VERSION 5.8 ;
BUSBITCHARS "[]" ;
DIVIDERCHAR "/" ;
UNITS
    DATABASE MICRONS 1000 ;
END UNITS

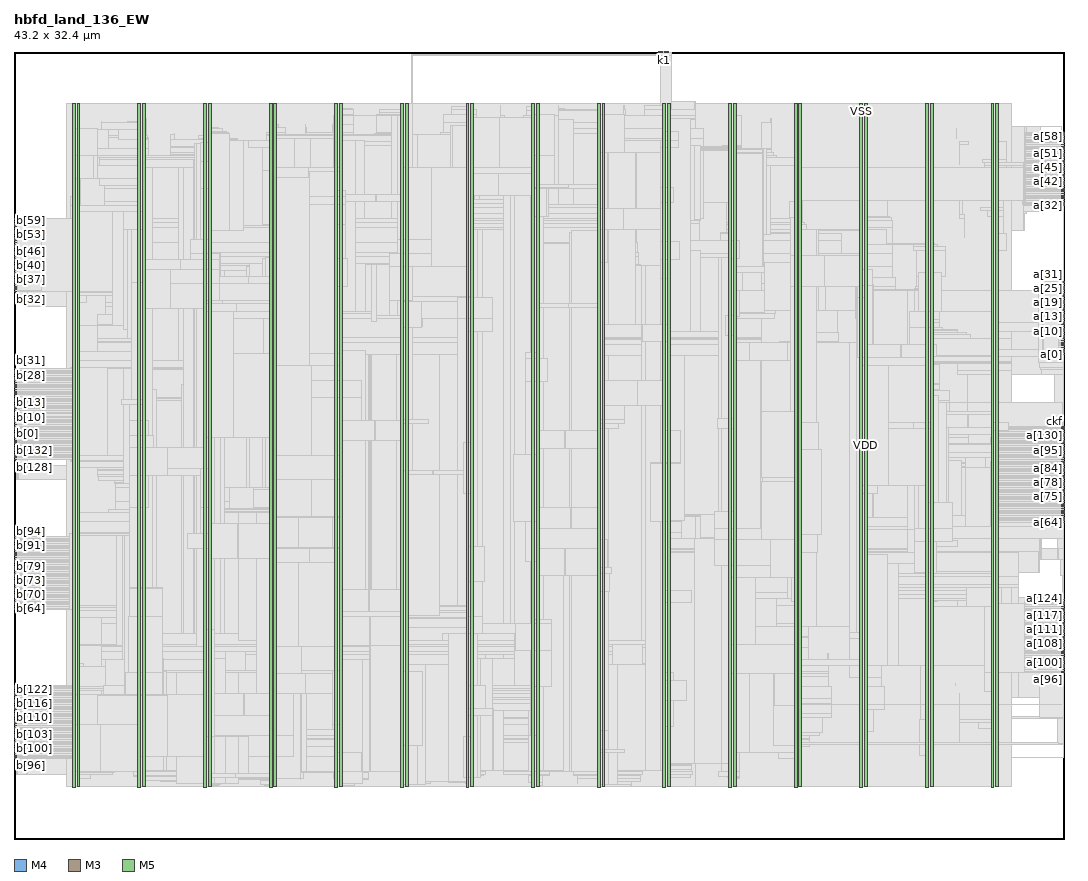
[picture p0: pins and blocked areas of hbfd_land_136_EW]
MACRO hbfd_land_136_EW
  FOREIGN hbfd_land_136_EW 0 0 ;
  CLASS BLOCK ;
  SIZE 43.2 BY 32.4 ;
  PIN a[0]
    DIRECTION INPUT ;
    USE SIGNAL ;
    PORT
      LAYER M4 ;
        RECT  43.116 19.92 43.2 19.944 ;
    END
  END a[0]
  PIN a[100]
    DIRECTION INPUT ;
    USE SIGNAL ;
    PORT
      LAYER M4 ;
        RECT  43.116 7.248 43.2 7.272 ;
    END
  END a[100]
  PIN a[101]
    DIRECTION INPUT ;
    USE SIGNAL ;
    PORT
      LAYER M4 ;
        RECT  43.116 7.344 43.2 7.368 ;
    END
  END a[101]
  PIN a[102]
    DIRECTION INPUT ;
    USE SIGNAL ;
    PORT
      LAYER M4 ;
        RECT  43.116 7.44 43.2 7.464 ;
    END
  END a[102]
  PIN a[103]
    DIRECTION INPUT ;
    USE SIGNAL ;
    PORT
      LAYER M4 ;
        RECT  43.116 7.536 43.2 7.56 ;
    END
  END a[103]
  PIN a[104]
    DIRECTION INPUT ;
    USE SIGNAL ;
    PORT
      LAYER M4 ;
        RECT  43.116 7.632 43.2 7.656 ;
    END
  END a[104]
  PIN a[105]
    DIRECTION INPUT ;
    USE SIGNAL ;
    PORT
      LAYER M4 ;
        RECT  43.116 7.728 43.2 7.752 ;
    END
  END a[105]
  PIN a[106]
    DIRECTION INPUT ;
    USE SIGNAL ;
    PORT
      LAYER M4 ;
        RECT  43.116 7.824 43.2 7.848 ;
    END
  END a[106]
  PIN a[107]
    DIRECTION INPUT ;
    USE SIGNAL ;
    PORT
      LAYER M4 ;
        RECT  43.116 7.92 43.2 7.944 ;
    END
  END a[107]
  PIN a[108]
    DIRECTION INPUT ;
    USE SIGNAL ;
    PORT
      LAYER M4 ;
        RECT  43.116 8.016 43.2 8.04 ;
    END
  END a[108]
  PIN a[109]
    DIRECTION INPUT ;
    USE SIGNAL ;
    PORT
      LAYER M4 ;
        RECT  43.116 8.112 43.2 8.136 ;
    END
  END a[109]
  PIN a[10]
    DIRECTION INPUT ;
    USE SIGNAL ;
    PORT
      LAYER M4 ;
        RECT  43.116 20.88 43.2 20.904 ;
    END
  END a[10]
  PIN a[110]
    DIRECTION INPUT ;
    USE SIGNAL ;
    PORT
      LAYER M4 ;
        RECT  43.116 8.208 43.2 8.232 ;
    END
  END a[110]
  PIN a[111]
    DIRECTION INPUT ;
    USE SIGNAL ;
    PORT
      LAYER M4 ;
        RECT  43.116 8.304 43.2 8.328 ;
    END
  END a[111]
  PIN a[112]
    DIRECTION INPUT ;
    USE SIGNAL ;
    PORT
      LAYER M4 ;
        RECT  43.116 8.4 43.2 8.424 ;
    END
  END a[112]
  PIN a[113]
    DIRECTION INPUT ;
    USE SIGNAL ;
    PORT
      LAYER M4 ;
        RECT  43.116 8.496 43.2 8.52 ;
    END
  END a[113]
  PIN a[114]
    DIRECTION INPUT ;
    USE SIGNAL ;
    PORT
      LAYER M4 ;
        RECT  43.116 8.592 43.2 8.616 ;
    END
  END a[114]
  PIN a[115]
    DIRECTION INPUT ;
    USE SIGNAL ;
    PORT
      LAYER M4 ;
        RECT  43.116 8.688 43.2 8.712 ;
    END
  END a[115]
  PIN a[116]
    DIRECTION INPUT ;
    USE SIGNAL ;
    PORT
      LAYER M4 ;
        RECT  43.116 8.784 43.2 8.808 ;
    END
  END a[116]
  PIN a[117]
    DIRECTION INPUT ;
    USE SIGNAL ;
    PORT
      LAYER M4 ;
        RECT  43.116 8.88 43.2 8.904 ;
    END
  END a[117]
  PIN a[118]
    DIRECTION INPUT ;
    USE SIGNAL ;
    PORT
      LAYER M4 ;
        RECT  43.116 8.976 43.2 9 ;
    END
  END a[118]
  PIN a[119]
    DIRECTION INPUT ;
    USE SIGNAL ;
    PORT
      LAYER M4 ;
        RECT  43.116 9.072 43.2 9.096 ;
    END
  END a[119]
  PIN a[11]
    DIRECTION INPUT ;
    USE SIGNAL ;
    PORT
      LAYER M4 ;
        RECT  43.116 20.976 43.2 21 ;
    END
  END a[11]
  PIN a[120]
    DIRECTION INPUT ;
    USE SIGNAL ;
    PORT
      LAYER M4 ;
        RECT  43.116 9.168 43.2 9.192 ;
    END
  END a[120]
  PIN a[121]
    DIRECTION INPUT ;
    USE SIGNAL ;
    PORT
      LAYER M4 ;
        RECT  43.116 9.264 43.2 9.288 ;
    END
  END a[121]
  PIN a[122]
    DIRECTION INPUT ;
    USE SIGNAL ;
    PORT
      LAYER M4 ;
        RECT  43.116 9.36 43.2 9.384 ;
    END
  END a[122]
  PIN a[123]
    DIRECTION INPUT ;
    USE SIGNAL ;
    PORT
      LAYER M4 ;
        RECT  43.116 9.456 43.2 9.48 ;
    END
  END a[123]
  PIN a[124]
    DIRECTION INPUT ;
    USE SIGNAL ;
    PORT
      LAYER M4 ;
        RECT  43.116 9.552 43.2 9.576 ;
    END
  END a[124]
  PIN a[125]
    DIRECTION INPUT ;
    USE SIGNAL ;
    PORT
      LAYER M4 ;
        RECT  43.116 9.648 43.2 9.672 ;
    END
  END a[125]
  PIN a[126]
    DIRECTION INPUT ;
    USE SIGNAL ;
    PORT
      LAYER M4 ;
        RECT  43.116 9.744 43.2 9.768 ;
    END
  END a[126]
  PIN a[127]
    DIRECTION INPUT ;
    USE SIGNAL ;
    PORT
      LAYER M4 ;
        RECT  43.116 9.84 43.2 9.864 ;
    END
  END a[127]
  PIN a[128]
    DIRECTION INPUT ;
    USE SIGNAL ;
    PORT
      LAYER M4 ;
        RECT  43.116 16.08 43.2 16.104 ;
    END
  END a[128]
  PIN a[129]
    DIRECTION INPUT ;
    USE SIGNAL ;
    PORT
      LAYER M4 ;
        RECT  43.116 16.176 43.2 16.2 ;
    END
  END a[129]
  PIN a[12]
    DIRECTION INPUT ;
    USE SIGNAL ;
    PORT
      LAYER M4 ;
        RECT  43.116 21.072 43.2 21.096 ;
    END
  END a[12]
  PIN a[130]
    DIRECTION INPUT ;
    USE SIGNAL ;
    PORT
      LAYER M4 ;
        RECT  43.116 16.272 43.2 16.296 ;
    END
  END a[130]
  PIN a[131]
    DIRECTION INPUT ;
    USE SIGNAL ;
    PORT
      LAYER M4 ;
        RECT  43.116 16.368 43.2 16.392 ;
    END
  END a[131]
  PIN a[132]
    DIRECTION INPUT ;
    USE SIGNAL ;
    PORT
      LAYER M4 ;
        RECT  43.116 16.464 43.2 16.488 ;
    END
  END a[132]
  PIN a[133]
    DIRECTION INPUT ;
    USE SIGNAL ;
    PORT
      LAYER M4 ;
        RECT  43.116 16.56 43.2 16.584 ;
    END
  END a[133]
  PIN a[134]
    DIRECTION INPUT ;
    USE SIGNAL ;
    PORT
      LAYER M4 ;
        RECT  43.116 16.656 43.2 16.68 ;
    END
  END a[134]
  PIN a[135]
    DIRECTION INPUT ;
    USE SIGNAL ;
    PORT
      LAYER M4 ;
        RECT  43.116 16.752 43.2 16.776 ;
    END
  END a[135]
  PIN a[13]
    DIRECTION INPUT ;
    USE SIGNAL ;
    PORT
      LAYER M4 ;
        RECT  43.116 21.168 43.2 21.192 ;
    END
  END a[13]
  PIN a[14]
    DIRECTION INPUT ;
    USE SIGNAL ;
    PORT
      LAYER M4 ;
        RECT  43.116 21.264 43.2 21.288 ;
    END
  END a[14]
  PIN a[15]
    DIRECTION INPUT ;
    USE SIGNAL ;
    PORT
      LAYER M4 ;
        RECT  43.116 21.36 43.2 21.384 ;
    END
  END a[15]
  PIN a[16]
    DIRECTION INPUT ;
    USE SIGNAL ;
    PORT
      LAYER M4 ;
        RECT  43.116 21.456 43.2 21.48 ;
    END
  END a[16]
  PIN a[17]
    DIRECTION INPUT ;
    USE SIGNAL ;
    PORT
      LAYER M4 ;
        RECT  43.116 21.552 43.2 21.576 ;
    END
  END a[17]
  PIN a[18]
    DIRECTION INPUT ;
    USE SIGNAL ;
    PORT
      LAYER M4 ;
        RECT  43.116 21.648 43.2 21.672 ;
    END
  END a[18]
  PIN a[19]
    DIRECTION INPUT ;
    USE SIGNAL ;
    PORT
      LAYER M4 ;
        RECT  43.116 21.744 43.2 21.768 ;
    END
  END a[19]
  PIN a[1]
    DIRECTION INPUT ;
    USE SIGNAL ;
    PORT
      LAYER M4 ;
        RECT  43.116 20.016 43.2 20.04 ;
    END
  END a[1]
  PIN a[20]
    DIRECTION INPUT ;
    USE SIGNAL ;
    PORT
      LAYER M4 ;
        RECT  43.116 21.84 43.2 21.864 ;
    END
  END a[20]
  PIN a[21]
    DIRECTION INPUT ;
    USE SIGNAL ;
    PORT
      LAYER M4 ;
        RECT  43.116 21.936 43.2 21.96 ;
    END
  END a[21]
  PIN a[22]
    DIRECTION INPUT ;
    USE SIGNAL ;
    PORT
      LAYER M4 ;
        RECT  43.116 22.032 43.2 22.056 ;
    END
  END a[22]
  PIN a[23]
    DIRECTION INPUT ;
    USE SIGNAL ;
    PORT
      LAYER M4 ;
        RECT  43.116 22.128 43.2 22.152 ;
    END
  END a[23]
  PIN a[24]
    DIRECTION INPUT ;
    USE SIGNAL ;
    PORT
      LAYER M4 ;
        RECT  43.116 22.224 43.2 22.248 ;
    END
  END a[24]
  PIN a[25]
    DIRECTION INPUT ;
    USE SIGNAL ;
    PORT
      LAYER M4 ;
        RECT  43.116 22.32 43.2 22.344 ;
    END
  END a[25]
  PIN a[26]
    DIRECTION INPUT ;
    USE SIGNAL ;
    PORT
      LAYER M4 ;
        RECT  43.116 22.416 43.2 22.44 ;
    END
  END a[26]
  PIN a[27]
    DIRECTION INPUT ;
    USE SIGNAL ;
    PORT
      LAYER M4 ;
        RECT  43.116 22.512 43.2 22.536 ;
    END
  END a[27]
  PIN a[28]
    DIRECTION INPUT ;
    USE SIGNAL ;
    PORT
      LAYER M4 ;
        RECT  43.116 22.608 43.2 22.632 ;
    END
  END a[28]
  PIN a[29]
    DIRECTION INPUT ;
    USE SIGNAL ;
    PORT
      LAYER M4 ;
        RECT  43.116 22.704 43.2 22.728 ;
    END
  END a[29]
  PIN a[2]
    DIRECTION INPUT ;
    USE SIGNAL ;
    PORT
      LAYER M4 ;
        RECT  43.116 20.112 43.2 20.136 ;
    END
  END a[2]
  PIN a[30]
    DIRECTION INPUT ;
    USE SIGNAL ;
    PORT
      LAYER M4 ;
        RECT  43.116 22.8 43.2 22.824 ;
    END
  END a[30]
  PIN a[31]
    DIRECTION INPUT ;
    USE SIGNAL ;
    PORT
      LAYER M4 ;
        RECT  43.116 22.896 43.2 22.92 ;
    END
  END a[31]
  PIN a[32]
    DIRECTION INPUT ;
    USE SIGNAL ;
    PORT
      LAYER M4 ;
        RECT  43.116 26.064 43.2 26.088 ;
    END
  END a[32]
  PIN a[33]
    DIRECTION INPUT ;
    USE SIGNAL ;
    PORT
      LAYER M4 ;
        RECT  43.116 26.16 43.2 26.184 ;
    END
  END a[33]
  PIN a[34]
    DIRECTION INPUT ;
    USE SIGNAL ;
    PORT
      LAYER M4 ;
        RECT  43.116 26.256 43.2 26.28 ;
    END
  END a[34]
  PIN a[35]
    DIRECTION INPUT ;
    USE SIGNAL ;
    PORT
      LAYER M4 ;
        RECT  43.116 26.352 43.2 26.376 ;
    END
  END a[35]
  PIN a[36]
    DIRECTION INPUT ;
    USE SIGNAL ;
    PORT
      LAYER M4 ;
        RECT  43.116 26.448 43.2 26.472 ;
    END
  END a[36]
  PIN a[37]
    DIRECTION INPUT ;
    USE SIGNAL ;
    PORT
      LAYER M4 ;
        RECT  43.116 26.544 43.2 26.568 ;
    END
  END a[37]
  PIN a[38]
    DIRECTION INPUT ;
    USE SIGNAL ;
    PORT
      LAYER M4 ;
        RECT  43.116 26.64 43.2 26.664 ;
    END
  END a[38]
  PIN a[39]
    DIRECTION INPUT ;
    USE SIGNAL ;
    PORT
      LAYER M4 ;
        RECT  43.116 26.736 43.2 26.76 ;
    END
  END a[39]
  PIN a[3]
    DIRECTION INPUT ;
    USE SIGNAL ;
    PORT
      LAYER M4 ;
        RECT  43.116 20.208 43.2 20.232 ;
    END
  END a[3]
  PIN a[40]
    DIRECTION INPUT ;
    USE SIGNAL ;
    PORT
      LAYER M4 ;
        RECT  43.116 26.832 43.2 26.856 ;
    END
  END a[40]
  PIN a[41]
    DIRECTION INPUT ;
    USE SIGNAL ;
    PORT
      LAYER M4 ;
        RECT  43.116 26.928 43.2 26.952 ;
    END
  END a[41]
  PIN a[42]
    DIRECTION INPUT ;
    USE SIGNAL ;
    PORT
      LAYER M4 ;
        RECT  43.116 27.024 43.2 27.048 ;
    END
  END a[42]
  PIN a[43]
    DIRECTION INPUT ;
    USE SIGNAL ;
    PORT
      LAYER M4 ;
        RECT  43.116 27.12 43.2 27.144 ;
    END
  END a[43]
  PIN a[44]
    DIRECTION INPUT ;
    USE SIGNAL ;
    PORT
      LAYER M4 ;
        RECT  43.116 27.216 43.2 27.24 ;
    END
  END a[44]
  PIN a[45]
    DIRECTION INPUT ;
    USE SIGNAL ;
    PORT
      LAYER M4 ;
        RECT  43.116 27.312 43.2 27.336 ;
    END
  END a[45]
  PIN a[46]
    DIRECTION INPUT ;
    USE SIGNAL ;
    PORT
      LAYER M4 ;
        RECT  43.116 27.408 43.2 27.432 ;
    END
  END a[46]
  PIN a[47]
    DIRECTION INPUT ;
    USE SIGNAL ;
    PORT
      LAYER M4 ;
        RECT  43.116 27.504 43.2 27.528 ;
    END
  END a[47]
  PIN a[48]
    DIRECTION INPUT ;
    USE SIGNAL ;
    PORT
      LAYER M4 ;
        RECT  43.116 27.6 43.2 27.624 ;
    END
  END a[48]
  PIN a[49]
    DIRECTION INPUT ;
    USE SIGNAL ;
    PORT
      LAYER M4 ;
        RECT  43.116 27.696 43.2 27.72 ;
    END
  END a[49]
  PIN a[4]
    DIRECTION INPUT ;
    USE SIGNAL ;
    PORT
      LAYER M4 ;
        RECT  43.116 20.304 43.2 20.328 ;
    END
  END a[4]
  PIN a[50]
    DIRECTION INPUT ;
    USE SIGNAL ;
    PORT
      LAYER M4 ;
        RECT  43.116 27.792 43.2 27.816 ;
    END
  END a[50]
  PIN a[51]
    DIRECTION INPUT ;
    USE SIGNAL ;
    PORT
      LAYER M4 ;
        RECT  43.116 27.888 43.2 27.912 ;
    END
  END a[51]
  PIN a[52]
    DIRECTION INPUT ;
    USE SIGNAL ;
    PORT
      LAYER M4 ;
        RECT  43.116 27.984 43.2 28.008 ;
    END
  END a[52]
  PIN a[53]
    DIRECTION INPUT ;
    USE SIGNAL ;
    PORT
      LAYER M4 ;
        RECT  43.116 28.08 43.2 28.104 ;
    END
  END a[53]
  PIN a[54]
    DIRECTION INPUT ;
    USE SIGNAL ;
    PORT
      LAYER M4 ;
        RECT  43.116 28.176 43.2 28.2 ;
    END
  END a[54]
  PIN a[55]
    DIRECTION INPUT ;
    USE SIGNAL ;
    PORT
      LAYER M4 ;
        RECT  43.116 28.272 43.2 28.296 ;
    END
  END a[55]
  PIN a[56]
    DIRECTION INPUT ;
    USE SIGNAL ;
    PORT
      LAYER M4 ;
        RECT  43.116 28.368 43.2 28.392 ;
    END
  END a[56]
  PIN a[57]
    DIRECTION INPUT ;
    USE SIGNAL ;
    PORT
      LAYER M4 ;
        RECT  43.116 28.464 43.2 28.488 ;
    END
  END a[57]
  PIN a[58]
    DIRECTION INPUT ;
    USE SIGNAL ;
    PORT
      LAYER M4 ;
        RECT  43.116 28.56 43.2 28.584 ;
    END
  END a[58]
  PIN a[59]
    DIRECTION INPUT ;
    USE SIGNAL ;
    PORT
      LAYER M4 ;
        RECT  43.116 28.656 43.2 28.68 ;
    END
  END a[59]
  PIN a[5]
    DIRECTION INPUT ;
    USE SIGNAL ;
    PORT
      LAYER M4 ;
        RECT  43.116 20.4 43.2 20.424 ;
    END
  END a[5]
  PIN a[60]
    DIRECTION INPUT ;
    USE SIGNAL ;
    PORT
      LAYER M4 ;
        RECT  43.116 28.752 43.2 28.776 ;
    END
  END a[60]
  PIN a[61]
    DIRECTION INPUT ;
    USE SIGNAL ;
    PORT
      LAYER M4 ;
        RECT  43.116 28.848 43.2 28.872 ;
    END
  END a[61]
  PIN a[62]
    DIRECTION INPUT ;
    USE SIGNAL ;
    PORT
      LAYER M4 ;
        RECT  43.116 28.944 43.2 28.968 ;
    END
  END a[62]
  PIN a[63]
    DIRECTION INPUT ;
    USE SIGNAL ;
    PORT
      LAYER M4 ;
        RECT  43.116 29.04 43.2 29.064 ;
    END
  END a[63]
  PIN a[64]
    DIRECTION INPUT ;
    USE SIGNAL ;
    PORT
      LAYER M4 ;
        RECT  43.116 13.008 43.2 13.032 ;
    END
  END a[64]
  PIN a[65]
    DIRECTION INPUT ;
    USE SIGNAL ;
    PORT
      LAYER M4 ;
        RECT  43.116 13.104 43.2 13.128 ;
    END
  END a[65]
  PIN a[66]
    DIRECTION INPUT ;
    USE SIGNAL ;
    PORT
      LAYER M4 ;
        RECT  43.116 13.2 43.2 13.224 ;
    END
  END a[66]
  PIN a[67]
    DIRECTION INPUT ;
    USE SIGNAL ;
    PORT
      LAYER M4 ;
        RECT  43.116 13.296 43.2 13.32 ;
    END
  END a[67]
  PIN a[68]
    DIRECTION INPUT ;
    USE SIGNAL ;
    PORT
      LAYER M4 ;
        RECT  43.116 13.392 43.2 13.416 ;
    END
  END a[68]
  PIN a[69]
    DIRECTION INPUT ;
    USE SIGNAL ;
    PORT
      LAYER M4 ;
        RECT  43.116 13.488 43.2 13.512 ;
    END
  END a[69]
  PIN a[6]
    DIRECTION INPUT ;
    USE SIGNAL ;
    PORT
      LAYER M4 ;
        RECT  43.116 20.496 43.2 20.52 ;
    END
  END a[6]
  PIN a[70]
    DIRECTION INPUT ;
    USE SIGNAL ;
    PORT
      LAYER M4 ;
        RECT  43.116 13.584 43.2 13.608 ;
    END
  END a[70]
  PIN a[71]
    DIRECTION INPUT ;
    USE SIGNAL ;
    PORT
      LAYER M4 ;
        RECT  43.116 13.68 43.2 13.704 ;
    END
  END a[71]
  PIN a[72]
    DIRECTION INPUT ;
    USE SIGNAL ;
    PORT
      LAYER M4 ;
        RECT  43.116 13.776 43.2 13.8 ;
    END
  END a[72]
  PIN a[73]
    DIRECTION INPUT ;
    USE SIGNAL ;
    PORT
      LAYER M4 ;
        RECT  43.116 13.872 43.2 13.896 ;
    END
  END a[73]
  PIN a[74]
    DIRECTION INPUT ;
    USE SIGNAL ;
    PORT
      LAYER M4 ;
        RECT  43.116 13.968 43.2 13.992 ;
    END
  END a[74]
  PIN a[75]
    DIRECTION INPUT ;
    USE SIGNAL ;
    PORT
      LAYER M4 ;
        RECT  43.116 14.064 43.2 14.088 ;
    END
  END a[75]
  PIN a[76]
    DIRECTION INPUT ;
    USE SIGNAL ;
    PORT
      LAYER M4 ;
        RECT  43.116 14.16 43.2 14.184 ;
    END
  END a[76]
  PIN a[77]
    DIRECTION INPUT ;
    USE SIGNAL ;
    PORT
      LAYER M4 ;
        RECT  43.116 14.256 43.2 14.28 ;
    END
  END a[77]
  PIN a[78]
    DIRECTION INPUT ;
    USE SIGNAL ;
    PORT
      LAYER M4 ;
        RECT  43.116 14.352 43.2 14.376 ;
    END
  END a[78]
  PIN a[79]
    DIRECTION INPUT ;
    USE SIGNAL ;
    PORT
      LAYER M4 ;
        RECT  43.116 14.448 43.2 14.472 ;
    END
  END a[79]
  PIN a[7]
    DIRECTION INPUT ;
    USE SIGNAL ;
    PORT
      LAYER M4 ;
        RECT  43.116 20.592 43.2 20.616 ;
    END
  END a[7]
  PIN a[80]
    DIRECTION INPUT ;
    USE SIGNAL ;
    PORT
      LAYER M4 ;
        RECT  43.116 14.544 43.2 14.568 ;
    END
  END a[80]
  PIN a[81]
    DIRECTION INPUT ;
    USE SIGNAL ;
    PORT
      LAYER M4 ;
        RECT  43.116 14.64 43.2 14.664 ;
    END
  END a[81]
  PIN a[82]
    DIRECTION INPUT ;
    USE SIGNAL ;
    PORT
      LAYER M4 ;
        RECT  43.116 14.736 43.2 14.76 ;
    END
  END a[82]
  PIN a[83]
    DIRECTION INPUT ;
    USE SIGNAL ;
    PORT
      LAYER M4 ;
        RECT  43.116 14.832 43.2 14.856 ;
    END
  END a[83]
  PIN a[84]
    DIRECTION INPUT ;
    USE SIGNAL ;
    PORT
      LAYER M4 ;
        RECT  43.116 14.928 43.2 14.952 ;
    END
  END a[84]
  PIN a[85]
    DIRECTION INPUT ;
    USE SIGNAL ;
    PORT
      LAYER M4 ;
        RECT  43.116 15.024 43.2 15.048 ;
    END
  END a[85]
  PIN a[86]
    DIRECTION INPUT ;
    USE SIGNAL ;
    PORT
      LAYER M4 ;
        RECT  43.116 15.12 43.2 15.144 ;
    END
  END a[86]
  PIN a[87]
    DIRECTION INPUT ;
    USE SIGNAL ;
    PORT
      LAYER M4 ;
        RECT  43.116 15.216 43.2 15.24 ;
    END
  END a[87]
  PIN a[88]
    DIRECTION INPUT ;
    USE SIGNAL ;
    PORT
      LAYER M4 ;
        RECT  43.116 15.312 43.2 15.336 ;
    END
  END a[88]
  PIN a[89]
    DIRECTION INPUT ;
    USE SIGNAL ;
    PORT
      LAYER M4 ;
        RECT  43.116 15.408 43.2 15.432 ;
    END
  END a[89]
  PIN a[8]
    DIRECTION INPUT ;
    USE SIGNAL ;
    PORT
      LAYER M4 ;
        RECT  43.116 20.688 43.2 20.712 ;
    END
  END a[8]
  PIN a[90]
    DIRECTION INPUT ;
    USE SIGNAL ;
    PORT
      LAYER M4 ;
        RECT  43.116 15.504 43.2 15.528 ;
    END
  END a[90]
  PIN a[91]
    DIRECTION INPUT ;
    USE SIGNAL ;
    PORT
      LAYER M4 ;
        RECT  43.116 15.6 43.2 15.624 ;
    END
  END a[91]
  PIN a[92]
    DIRECTION INPUT ;
    USE SIGNAL ;
    PORT
      LAYER M4 ;
        RECT  43.116 15.696 43.2 15.72 ;
    END
  END a[92]
  PIN a[93]
    DIRECTION INPUT ;
    USE SIGNAL ;
    PORT
      LAYER M4 ;
        RECT  43.116 15.792 43.2 15.816 ;
    END
  END a[93]
  PIN a[94]
    DIRECTION INPUT ;
    USE SIGNAL ;
    PORT
      LAYER M4 ;
        RECT  43.116 15.888 43.2 15.912 ;
    END
  END a[94]
  PIN a[95]
    DIRECTION INPUT ;
    USE SIGNAL ;
    PORT
      LAYER M4 ;
        RECT  43.116 15.984 43.2 16.008 ;
    END
  END a[95]
  PIN a[96]
    DIRECTION INPUT ;
    USE SIGNAL ;
    PORT
      LAYER M4 ;
        RECT  43.116 6.864 43.2 6.888 ;
    END
  END a[96]
  PIN a[97]
    DIRECTION INPUT ;
    USE SIGNAL ;
    PORT
      LAYER M4 ;
        RECT  43.116 6.96 43.2 6.984 ;
    END
  END a[97]
  PIN a[98]
    DIRECTION INPUT ;
    USE SIGNAL ;
    PORT
      LAYER M4 ;
        RECT  43.116 7.056 43.2 7.08 ;
    END
  END a[98]
  PIN a[99]
    DIRECTION INPUT ;
    USE SIGNAL ;
    PORT
      LAYER M4 ;
        RECT  43.116 7.152 43.2 7.176 ;
    END
  END a[99]
  PIN a[9]
    DIRECTION INPUT ;
    USE SIGNAL ;
    PORT
      LAYER M4 ;
        RECT  43.116 20.784 43.2 20.808 ;
    END
  END a[9]
  PIN b[0]
    DIRECTION OUTPUT ;
    USE SIGNAL ;
    PORT
      LAYER M4 ;
        RECT  0 16.368 0.084 16.392 ;
    END
  END b[0]
  PIN b[100]
    DIRECTION OUTPUT ;
    USE SIGNAL ;
    PORT
      LAYER M4 ;
        RECT  0 3.696 0.084 3.72 ;
    END
  END b[100]
  PIN b[101]
    DIRECTION OUTPUT ;
    USE SIGNAL ;
    PORT
      LAYER M4 ;
        RECT  0 3.792 0.084 3.816 ;
    END
  END b[101]
  PIN b[102]
    DIRECTION OUTPUT ;
    USE SIGNAL ;
    PORT
      LAYER M4 ;
        RECT  0 3.888 0.084 3.912 ;
    END
  END b[102]
  PIN b[103]
    DIRECTION OUTPUT ;
    USE SIGNAL ;
    PORT
      LAYER M4 ;
        RECT  0 3.984 0.084 4.008 ;
    END
  END b[103]
  PIN b[104]
    DIRECTION OUTPUT ;
    USE SIGNAL ;
    PORT
      LAYER M4 ;
        RECT  0 4.08 0.084 4.104 ;
    END
  END b[104]
  PIN b[105]
    DIRECTION OUTPUT ;
    USE SIGNAL ;
    PORT
      LAYER M4 ;
        RECT  0 4.176 0.084 4.2 ;
    END
  END b[105]
  PIN b[106]
    DIRECTION OUTPUT ;
    USE SIGNAL ;
    PORT
      LAYER M4 ;
        RECT  0 4.272 0.084 4.296 ;
    END
  END b[106]
  PIN b[107]
    DIRECTION OUTPUT ;
    USE SIGNAL ;
    PORT
      LAYER M4 ;
        RECT  0 4.368 0.084 4.392 ;
    END
  END b[107]
  PIN b[108]
    DIRECTION OUTPUT ;
    USE SIGNAL ;
    PORT
      LAYER M4 ;
        RECT  0 4.464 0.084 4.488 ;
    END
  END b[108]
  PIN b[109]
    DIRECTION OUTPUT ;
    USE SIGNAL ;
    PORT
      LAYER M4 ;
        RECT  0 4.56 0.084 4.584 ;
    END
  END b[109]
  PIN b[10]
    DIRECTION OUTPUT ;
    USE SIGNAL ;
    PORT
      LAYER M4 ;
        RECT  0 17.328 0.084 17.352 ;
    END
  END b[10]
  PIN b[110]
    DIRECTION OUTPUT ;
    USE SIGNAL ;
    PORT
      LAYER M4 ;
        RECT  0 4.656 0.084 4.68 ;
    END
  END b[110]
  PIN b[111]
    DIRECTION OUTPUT ;
    USE SIGNAL ;
    PORT
      LAYER M4 ;
        RECT  0 4.752 0.084 4.776 ;
    END
  END b[111]
  PIN b[112]
    DIRECTION OUTPUT ;
    USE SIGNAL ;
    PORT
      LAYER M4 ;
        RECT  0 4.848 0.084 4.872 ;
    END
  END b[112]
  PIN b[113]
    DIRECTION OUTPUT ;
    USE SIGNAL ;
    PORT
      LAYER M4 ;
        RECT  0 4.944 0.084 4.968 ;
    END
  END b[113]
  PIN b[114]
    DIRECTION OUTPUT ;
    USE SIGNAL ;
    PORT
      LAYER M4 ;
        RECT  0 5.04 0.084 5.064 ;
    END
  END b[114]
  PIN b[115]
    DIRECTION OUTPUT ;
    USE SIGNAL ;
    PORT
      LAYER M4 ;
        RECT  0 5.136 0.084 5.16 ;
    END
  END b[115]
  PIN b[116]
    DIRECTION OUTPUT ;
    USE SIGNAL ;
    PORT
      LAYER M4 ;
        RECT  0 5.232 0.084 5.256 ;
    END
  END b[116]
  PIN b[117]
    DIRECTION OUTPUT ;
    USE SIGNAL ;
    PORT
      LAYER M4 ;
        RECT  0 5.328 0.084 5.352 ;
    END
  END b[117]
  PIN b[118]
    DIRECTION OUTPUT ;
    USE SIGNAL ;
    PORT
      LAYER M4 ;
        RECT  0 5.424 0.084 5.448 ;
    END
  END b[118]
  PIN b[119]
    DIRECTION OUTPUT ;
    USE SIGNAL ;
    PORT
      LAYER M4 ;
        RECT  0 5.52 0.084 5.544 ;
    END
  END b[119]
  PIN b[11]
    DIRECTION OUTPUT ;
    USE SIGNAL ;
    PORT
      LAYER M4 ;
        RECT  0 17.424 0.084 17.448 ;
    END
  END b[11]
  PIN b[120]
    DIRECTION OUTPUT ;
    USE SIGNAL ;
    PORT
      LAYER M4 ;
        RECT  0 5.616 0.084 5.64 ;
    END
  END b[120]
  PIN b[121]
    DIRECTION OUTPUT ;
    USE SIGNAL ;
    PORT
      LAYER M4 ;
        RECT  0 5.712 0.084 5.736 ;
    END
  END b[121]
  PIN b[122]
    DIRECTION OUTPUT ;
    USE SIGNAL ;
    PORT
      LAYER M4 ;
        RECT  0 5.808 0.084 5.832 ;
    END
  END b[122]
  PIN b[123]
    DIRECTION OUTPUT ;
    USE SIGNAL ;
    PORT
      LAYER M4 ;
        RECT  0 5.904 0.084 5.928 ;
    END
  END b[123]
  PIN b[124]
    DIRECTION OUTPUT ;
    USE SIGNAL ;
    PORT
      LAYER M4 ;
        RECT  0 6 0.084 6.024 ;
    END
  END b[124]
  PIN b[125]
    DIRECTION OUTPUT ;
    USE SIGNAL ;
    PORT
      LAYER M4 ;
        RECT  0 6.096 0.084 6.12 ;
    END
  END b[125]
  PIN b[126]
    DIRECTION OUTPUT ;
    USE SIGNAL ;
    PORT
      LAYER M4 ;
        RECT  0 6.192 0.084 6.216 ;
    END
  END b[126]
  PIN b[127]
    DIRECTION OUTPUT ;
    USE SIGNAL ;
    PORT
      LAYER M4 ;
        RECT  0 6.288 0.084 6.312 ;
    END
  END b[127]
  PIN b[128]
    DIRECTION OUTPUT ;
    USE SIGNAL ;
    PORT
      LAYER M4 ;
        RECT  0 15.6 0.084 15.624 ;
    END
  END b[128]
  PIN b[129]
    DIRECTION OUTPUT ;
    USE SIGNAL ;
    PORT
      LAYER M4 ;
        RECT  0 15.696 0.084 15.72 ;
    END
  END b[129]
  PIN b[12]
    DIRECTION OUTPUT ;
    USE SIGNAL ;
    PORT
      LAYER M4 ;
        RECT  0 17.52 0.084 17.544 ;
    END
  END b[12]
  PIN b[130]
    DIRECTION OUTPUT ;
    USE SIGNAL ;
    PORT
      LAYER M4 ;
        RECT  0 15.792 0.084 15.816 ;
    END
  END b[130]
  PIN b[131]
    DIRECTION OUTPUT ;
    USE SIGNAL ;
    PORT
      LAYER M4 ;
        RECT  0 15.888 0.084 15.912 ;
    END
  END b[131]
  PIN b[132]
    DIRECTION OUTPUT ;
    USE SIGNAL ;
    PORT
      LAYER M4 ;
        RECT  0 15.984 0.084 16.008 ;
    END
  END b[132]
  PIN b[133]
    DIRECTION OUTPUT ;
    USE SIGNAL ;
    PORT
      LAYER M4 ;
        RECT  0 16.08 0.084 16.104 ;
    END
  END b[133]
  PIN b[134]
    DIRECTION OUTPUT ;
    USE SIGNAL ;
    PORT
      LAYER M4 ;
        RECT  0 16.176 0.084 16.2 ;
    END
  END b[134]
  PIN b[135]
    DIRECTION OUTPUT ;
    USE SIGNAL ;
    PORT
      LAYER M4 ;
        RECT  0 16.272 0.084 16.296 ;
    END
  END b[135]
  PIN b[13]
    DIRECTION OUTPUT ;
    USE SIGNAL ;
    PORT
      LAYER M4 ;
        RECT  0 17.616 0.084 17.64 ;
    END
  END b[13]
  PIN b[14]
    DIRECTION OUTPUT ;
    USE SIGNAL ;
    PORT
      LAYER M4 ;
        RECT  0 17.712 0.084 17.736 ;
    END
  END b[14]
  PIN b[15]
    DIRECTION OUTPUT ;
    USE SIGNAL ;
    PORT
      LAYER M4 ;
        RECT  0 17.808 0.084 17.832 ;
    END
  END b[15]
  PIN b[16]
    DIRECTION OUTPUT ;
    USE SIGNAL ;
    PORT
      LAYER M4 ;
        RECT  0 17.904 0.084 17.928 ;
    END
  END b[16]
  PIN b[17]
    DIRECTION OUTPUT ;
    USE SIGNAL ;
    PORT
      LAYER M4 ;
        RECT  0 18 0.084 18.024 ;
    END
  END b[17]
  PIN b[18]
    DIRECTION OUTPUT ;
    USE SIGNAL ;
    PORT
      LAYER M4 ;
        RECT  0 18.096 0.084 18.12 ;
    END
  END b[18]
  PIN b[19]
    DIRECTION OUTPUT ;
    USE SIGNAL ;
    PORT
      LAYER M4 ;
        RECT  0 18.192 0.084 18.216 ;
    END
  END b[19]
  PIN b[1]
    DIRECTION OUTPUT ;
    USE SIGNAL ;
    PORT
      LAYER M4 ;
        RECT  0 16.464 0.084 16.488 ;
    END
  END b[1]
  PIN b[20]
    DIRECTION OUTPUT ;
    USE SIGNAL ;
    PORT
      LAYER M4 ;
        RECT  0 18.288 0.084 18.312 ;
    END
  END b[20]
  PIN b[21]
    DIRECTION OUTPUT ;
    USE SIGNAL ;
    PORT
      LAYER M4 ;
        RECT  0 18.384 0.084 18.408 ;
    END
  END b[21]
  PIN b[22]
    DIRECTION OUTPUT ;
    USE SIGNAL ;
    PORT
      LAYER M4 ;
        RECT  0 18.48 0.084 18.504 ;
    END
  END b[22]
  PIN b[23]
    DIRECTION OUTPUT ;
    USE SIGNAL ;
    PORT
      LAYER M4 ;
        RECT  0 18.576 0.084 18.6 ;
    END
  END b[23]
  PIN b[24]
    DIRECTION OUTPUT ;
    USE SIGNAL ;
    PORT
      LAYER M4 ;
        RECT  0 18.672 0.084 18.696 ;
    END
  END b[24]
  PIN b[25]
    DIRECTION OUTPUT ;
    USE SIGNAL ;
    PORT
      LAYER M4 ;
        RECT  0 18.768 0.084 18.792 ;
    END
  END b[25]
  PIN b[26]
    DIRECTION OUTPUT ;
    USE SIGNAL ;
    PORT
      LAYER M4 ;
        RECT  0 18.864 0.084 18.888 ;
    END
  END b[26]
  PIN b[27]
    DIRECTION OUTPUT ;
    USE SIGNAL ;
    PORT
      LAYER M4 ;
        RECT  0 18.96 0.084 18.984 ;
    END
  END b[27]
  PIN b[28]
    DIRECTION OUTPUT ;
    USE SIGNAL ;
    PORT
      LAYER M4 ;
        RECT  0 19.056 0.084 19.08 ;
    END
  END b[28]
  PIN b[29]
    DIRECTION OUTPUT ;
    USE SIGNAL ;
    PORT
      LAYER M4 ;
        RECT  0 19.152 0.084 19.176 ;
    END
  END b[29]
  PIN b[2]
    DIRECTION OUTPUT ;
    USE SIGNAL ;
    PORT
      LAYER M4 ;
        RECT  0 16.56 0.084 16.584 ;
    END
  END b[2]
  PIN b[30]
    DIRECTION OUTPUT ;
    USE SIGNAL ;
    PORT
      LAYER M4 ;
        RECT  0 19.248 0.084 19.272 ;
    END
  END b[30]
  PIN b[31]
    DIRECTION OUTPUT ;
    USE SIGNAL ;
    PORT
      LAYER M4 ;
        RECT  0 19.344 0.084 19.368 ;
    END
  END b[31]
  PIN b[32]
    DIRECTION OUTPUT ;
    USE SIGNAL ;
    PORT
      LAYER M4 ;
        RECT  0 22.512 0.084 22.536 ;
    END
  END b[32]
  PIN b[33]
    DIRECTION OUTPUT ;
    USE SIGNAL ;
    PORT
      LAYER M4 ;
        RECT  0 22.608 0.084 22.632 ;
    END
  END b[33]
  PIN b[34]
    DIRECTION OUTPUT ;
    USE SIGNAL ;
    PORT
      LAYER M4 ;
        RECT  0 22.704 0.084 22.728 ;
    END
  END b[34]
  PIN b[35]
    DIRECTION OUTPUT ;
    USE SIGNAL ;
    PORT
      LAYER M4 ;
        RECT  0 22.8 0.084 22.824 ;
    END
  END b[35]
  PIN b[36]
    DIRECTION OUTPUT ;
    USE SIGNAL ;
    PORT
      LAYER M4 ;
        RECT  0 22.896 0.084 22.92 ;
    END
  END b[36]
  PIN b[37]
    DIRECTION OUTPUT ;
    USE SIGNAL ;
    PORT
      LAYER M4 ;
        RECT  0 22.992 0.084 23.016 ;
    END
  END b[37]
  PIN b[38]
    DIRECTION OUTPUT ;
    USE SIGNAL ;
    PORT
      LAYER M4 ;
        RECT  0 23.088 0.084 23.112 ;
    END
  END b[38]
  PIN b[39]
    DIRECTION OUTPUT ;
    USE SIGNAL ;
    PORT
      LAYER M4 ;
        RECT  0 23.184 0.084 23.208 ;
    END
  END b[39]
  PIN b[3]
    DIRECTION OUTPUT ;
    USE SIGNAL ;
    PORT
      LAYER M4 ;
        RECT  0 16.656 0.084 16.68 ;
    END
  END b[3]
  PIN b[40]
    DIRECTION OUTPUT ;
    USE SIGNAL ;
    PORT
      LAYER M4 ;
        RECT  0 23.28 0.084 23.304 ;
    END
  END b[40]
  PIN b[41]
    DIRECTION OUTPUT ;
    USE SIGNAL ;
    PORT
      LAYER M4 ;
        RECT  0 23.376 0.084 23.4 ;
    END
  END b[41]
  PIN b[42]
    DIRECTION OUTPUT ;
    USE SIGNAL ;
    PORT
      LAYER M4 ;
        RECT  0 23.472 0.084 23.496 ;
    END
  END b[42]
  PIN b[43]
    DIRECTION OUTPUT ;
    USE SIGNAL ;
    PORT
      LAYER M4 ;
        RECT  0 23.568 0.084 23.592 ;
    END
  END b[43]
  PIN b[44]
    DIRECTION OUTPUT ;
    USE SIGNAL ;
    PORT
      LAYER M4 ;
        RECT  0 23.664 0.084 23.688 ;
    END
  END b[44]
  PIN b[45]
    DIRECTION OUTPUT ;
    USE SIGNAL ;
    PORT
      LAYER M4 ;
        RECT  0 23.76 0.084 23.784 ;
    END
  END b[45]
  PIN b[46]
    DIRECTION OUTPUT ;
    USE SIGNAL ;
    PORT
      LAYER M4 ;
        RECT  0 23.856 0.084 23.88 ;
    END
  END b[46]
  PIN b[47]
    DIRECTION OUTPUT ;
    USE SIGNAL ;
    PORT
      LAYER M4 ;
        RECT  0 23.952 0.084 23.976 ;
    END
  END b[47]
  PIN b[48]
    DIRECTION OUTPUT ;
    USE SIGNAL ;
    PORT
      LAYER M4 ;
        RECT  0 24.048 0.084 24.072 ;
    END
  END b[48]
  PIN b[49]
    DIRECTION OUTPUT ;
    USE SIGNAL ;
    PORT
      LAYER M4 ;
        RECT  0 24.144 0.084 24.168 ;
    END
  END b[49]
  PIN b[4]
    DIRECTION OUTPUT ;
    USE SIGNAL ;
    PORT
      LAYER M4 ;
        RECT  0 16.752 0.084 16.776 ;
    END
  END b[4]
  PIN b[50]
    DIRECTION OUTPUT ;
    USE SIGNAL ;
    PORT
      LAYER M4 ;
        RECT  0 24.24 0.084 24.264 ;
    END
  END b[50]
  PIN b[51]
    DIRECTION OUTPUT ;
    USE SIGNAL ;
    PORT
      LAYER M4 ;
        RECT  0 24.336 0.084 24.36 ;
    END
  END b[51]
  PIN b[52]
    DIRECTION OUTPUT ;
    USE SIGNAL ;
    PORT
      LAYER M4 ;
        RECT  0 24.432 0.084 24.456 ;
    END
  END b[52]
  PIN b[53]
    DIRECTION OUTPUT ;
    USE SIGNAL ;
    PORT
      LAYER M4 ;
        RECT  0 24.528 0.084 24.552 ;
    END
  END b[53]
  PIN b[54]
    DIRECTION OUTPUT ;
    USE SIGNAL ;
    PORT
      LAYER M4 ;
        RECT  0 24.624 0.084 24.648 ;
    END
  END b[54]
  PIN b[55]
    DIRECTION OUTPUT ;
    USE SIGNAL ;
    PORT
      LAYER M4 ;
        RECT  0 24.72 0.084 24.744 ;
    END
  END b[55]
  PIN b[56]
    DIRECTION OUTPUT ;
    USE SIGNAL ;
    PORT
      LAYER M4 ;
        RECT  0 24.816 0.084 24.84 ;
    END
  END b[56]
  PIN b[57]
    DIRECTION OUTPUT ;
    USE SIGNAL ;
    PORT
      LAYER M4 ;
        RECT  0 24.912 0.084 24.936 ;
    END
  END b[57]
  PIN b[58]
    DIRECTION OUTPUT ;
    USE SIGNAL ;
    PORT
      LAYER M4 ;
        RECT  0 25.008 0.084 25.032 ;
    END
  END b[58]
  PIN b[59]
    DIRECTION OUTPUT ;
    USE SIGNAL ;
    PORT
      LAYER M4 ;
        RECT  0 25.104 0.084 25.128 ;
    END
  END b[59]
  PIN b[5]
    DIRECTION OUTPUT ;
    USE SIGNAL ;
    PORT
      LAYER M4 ;
        RECT  0 16.848 0.084 16.872 ;
    END
  END b[5]
  PIN b[60]
    DIRECTION OUTPUT ;
    USE SIGNAL ;
    PORT
      LAYER M4 ;
        RECT  0 25.2 0.084 25.224 ;
    END
  END b[60]
  PIN b[61]
    DIRECTION OUTPUT ;
    USE SIGNAL ;
    PORT
      LAYER M4 ;
        RECT  0 25.296 0.084 25.32 ;
    END
  END b[61]
  PIN b[62]
    DIRECTION OUTPUT ;
    USE SIGNAL ;
    PORT
      LAYER M4 ;
        RECT  0 25.392 0.084 25.416 ;
    END
  END b[62]
  PIN b[63]
    DIRECTION OUTPUT ;
    USE SIGNAL ;
    PORT
      LAYER M4 ;
        RECT  0 25.488 0.084 25.512 ;
    END
  END b[63]
  PIN b[64]
    DIRECTION OUTPUT ;
    USE SIGNAL ;
    PORT
      LAYER M4 ;
        RECT  0 9.456 0.084 9.48 ;
    END
  END b[64]
  PIN b[65]
    DIRECTION OUTPUT ;
    USE SIGNAL ;
    PORT
      LAYER M4 ;
        RECT  0 9.552 0.084 9.576 ;
    END
  END b[65]
  PIN b[66]
    DIRECTION OUTPUT ;
    USE SIGNAL ;
    PORT
      LAYER M4 ;
        RECT  0 9.648 0.084 9.672 ;
    END
  END b[66]
  PIN b[67]
    DIRECTION OUTPUT ;
    USE SIGNAL ;
    PORT
      LAYER M4 ;
        RECT  0 9.744 0.084 9.768 ;
    END
  END b[67]
  PIN b[68]
    DIRECTION OUTPUT ;
    USE SIGNAL ;
    PORT
      LAYER M4 ;
        RECT  0 9.84 0.084 9.864 ;
    END
  END b[68]
  PIN b[69]
    DIRECTION OUTPUT ;
    USE SIGNAL ;
    PORT
      LAYER M4 ;
        RECT  0 9.936 0.084 9.96 ;
    END
  END b[69]
  PIN b[6]
    DIRECTION OUTPUT ;
    USE SIGNAL ;
    PORT
      LAYER M4 ;
        RECT  0 16.944 0.084 16.968 ;
    END
  END b[6]
  PIN b[70]
    DIRECTION OUTPUT ;
    USE SIGNAL ;
    PORT
      LAYER M4 ;
        RECT  0 10.032 0.084 10.056 ;
    END
  END b[70]
  PIN b[71]
    DIRECTION OUTPUT ;
    USE SIGNAL ;
    PORT
      LAYER M4 ;
        RECT  0 10.128 0.084 10.152 ;
    END
  END b[71]
  PIN b[72]
    DIRECTION OUTPUT ;
    USE SIGNAL ;
    PORT
      LAYER M4 ;
        RECT  0 10.224 0.084 10.248 ;
    END
  END b[72]
  PIN b[73]
    DIRECTION OUTPUT ;
    USE SIGNAL ;
    PORT
      LAYER M4 ;
        RECT  0 10.32 0.084 10.344 ;
    END
  END b[73]
  PIN b[74]
    DIRECTION OUTPUT ;
    USE SIGNAL ;
    PORT
      LAYER M4 ;
        RECT  0 10.416 0.084 10.44 ;
    END
  END b[74]
  PIN b[75]
    DIRECTION OUTPUT ;
    USE SIGNAL ;
    PORT
      LAYER M4 ;
        RECT  0 10.512 0.084 10.536 ;
    END
  END b[75]
  PIN b[76]
    DIRECTION OUTPUT ;
    USE SIGNAL ;
    PORT
      LAYER M4 ;
        RECT  0 10.608 0.084 10.632 ;
    END
  END b[76]
  PIN b[77]
    DIRECTION OUTPUT ;
    USE SIGNAL ;
    PORT
      LAYER M4 ;
        RECT  0 10.704 0.084 10.728 ;
    END
  END b[77]
  PIN b[78]
    DIRECTION OUTPUT ;
    USE SIGNAL ;
    PORT
      LAYER M4 ;
        RECT  0 10.8 0.084 10.824 ;
    END
  END b[78]
  PIN b[79]
    DIRECTION OUTPUT ;
    USE SIGNAL ;
    PORT
      LAYER M4 ;
        RECT  0 10.896 0.084 10.92 ;
    END
  END b[79]
  PIN b[7]
    DIRECTION OUTPUT ;
    USE SIGNAL ;
    PORT
      LAYER M4 ;
        RECT  0 17.04 0.084 17.064 ;
    END
  END b[7]
  PIN b[80]
    DIRECTION OUTPUT ;
    USE SIGNAL ;
    PORT
      LAYER M4 ;
        RECT  0 10.992 0.084 11.016 ;
    END
  END b[80]
  PIN b[81]
    DIRECTION OUTPUT ;
    USE SIGNAL ;
    PORT
      LAYER M4 ;
        RECT  0 11.088 0.084 11.112 ;
    END
  END b[81]
  PIN b[82]
    DIRECTION OUTPUT ;
    USE SIGNAL ;
    PORT
      LAYER M4 ;
        RECT  0 11.184 0.084 11.208 ;
    END
  END b[82]
  PIN b[83]
    DIRECTION OUTPUT ;
    USE SIGNAL ;
    PORT
      LAYER M4 ;
        RECT  0 11.28 0.084 11.304 ;
    END
  END b[83]
  PIN b[84]
    DIRECTION OUTPUT ;
    USE SIGNAL ;
    PORT
      LAYER M4 ;
        RECT  0 11.376 0.084 11.4 ;
    END
  END b[84]
  PIN b[85]
    DIRECTION OUTPUT ;
    USE SIGNAL ;
    PORT
      LAYER M4 ;
        RECT  0 11.472 0.084 11.496 ;
    END
  END b[85]
  PIN b[86]
    DIRECTION OUTPUT ;
    USE SIGNAL ;
    PORT
      LAYER M4 ;
        RECT  0 11.568 0.084 11.592 ;
    END
  END b[86]
  PIN b[87]
    DIRECTION OUTPUT ;
    USE SIGNAL ;
    PORT
      LAYER M4 ;
        RECT  0 11.664 0.084 11.688 ;
    END
  END b[87]
  PIN b[88]
    DIRECTION OUTPUT ;
    USE SIGNAL ;
    PORT
      LAYER M4 ;
        RECT  0 11.76 0.084 11.784 ;
    END
  END b[88]
  PIN b[89]
    DIRECTION OUTPUT ;
    USE SIGNAL ;
    PORT
      LAYER M4 ;
        RECT  0 11.856 0.084 11.88 ;
    END
  END b[89]
  PIN b[8]
    DIRECTION OUTPUT ;
    USE SIGNAL ;
    PORT
      LAYER M4 ;
        RECT  0 17.136 0.084 17.16 ;
    END
  END b[8]
  PIN b[90]
    DIRECTION OUTPUT ;
    USE SIGNAL ;
    PORT
      LAYER M4 ;
        RECT  0 11.952 0.084 11.976 ;
    END
  END b[90]
  PIN b[91]
    DIRECTION OUTPUT ;
    USE SIGNAL ;
    PORT
      LAYER M4 ;
        RECT  0 12.048 0.084 12.072 ;
    END
  END b[91]
  PIN b[92]
    DIRECTION OUTPUT ;
    USE SIGNAL ;
    PORT
      LAYER M4 ;
        RECT  0 12.144 0.084 12.168 ;
    END
  END b[92]
  PIN b[93]
    DIRECTION OUTPUT ;
    USE SIGNAL ;
    PORT
      LAYER M4 ;
        RECT  0 12.24 0.084 12.264 ;
    END
  END b[93]
  PIN b[94]
    DIRECTION OUTPUT ;
    USE SIGNAL ;
    PORT
      LAYER M4 ;
        RECT  0 12.336 0.084 12.36 ;
    END
  END b[94]
  PIN b[95]
    DIRECTION OUTPUT ;
    USE SIGNAL ;
    PORT
      LAYER M4 ;
        RECT  0 12.432 0.084 12.456 ;
    END
  END b[95]
  PIN b[96]
    DIRECTION OUTPUT ;
    USE SIGNAL ;
    PORT
      LAYER M4 ;
        RECT  0 3.312 0.084 3.336 ;
    END
  END b[96]
  PIN b[97]
    DIRECTION OUTPUT ;
    USE SIGNAL ;
    PORT
      LAYER M4 ;
        RECT  0 3.408 0.084 3.432 ;
    END
  END b[97]
  PIN b[98]
    DIRECTION OUTPUT ;
    USE SIGNAL ;
    PORT
      LAYER M4 ;
        RECT  0 3.504 0.084 3.528 ;
    END
  END b[98]
  PIN b[99]
    DIRECTION OUTPUT ;
    USE SIGNAL ;
    PORT
      LAYER M4 ;
        RECT  0 3.6 0.084 3.624 ;
    END
  END b[99]
  PIN b[9]
    DIRECTION OUTPUT ;
    USE SIGNAL ;
    PORT
      LAYER M4 ;
        RECT  0 17.232 0.084 17.256 ;
    END
  END b[9]
  PIN ck
    DIRECTION INPUT ;
    USE SIGNAL ;
    PORT
      LAYER M3 ;
        RECT  26.532 32.363 26.55 32.4 ;
    END
  END ck
  PIN ckf
    DIRECTION INPUT ;
    USE SIGNAL ;
    PORT
      LAYER M4 ;
        RECT  43.116 16.848 43.2 16.872 ;
    END
  END ckf
  PIN ea
    DIRECTION INPUT ;
    USE SIGNAL ;
    PORT
      LAYER M4 ;
        RECT  43.116 16.944 43.2 16.968 ;
    END
  END ea
  PIN fault
    DIRECTION OUTPUT ;
    USE SIGNAL ;
    PORT
      LAYER M3 ;
        RECT  26.604 32.363 26.622 32.4 ;
    END
  END fault
  PIN k0
    DIRECTION INPUT ;
    USE SIGNAL ;
    PORT
      LAYER M3 ;
        RECT  26.676 32.363 26.694 32.4 ;
    END
  END k0
  PIN k1
    DIRECTION INPUT ;
    USE SIGNAL ;
    PORT
      LAYER M3 ;
        RECT  26.748 32.363 26.766 32.4 ;
    END
  END k1
  PIN k2
    DIRECTION INPUT ;
    USE SIGNAL ;
    PORT
      LAYER M3 ;
        RECT  26.82 32.363 26.838 32.4 ;
    END
  END k2
  PIN rs
    DIRECTION INPUT ;
    USE SIGNAL ;
    PORT
      LAYER M3 ;
        RECT  26.892 32.363 26.91 32.4 ;
    END
  END rs
  PIN VDD
    DIRECTION INOUT ;
    USE POWER ;
    PORT
      LAYER M5 ;
        RECT  40.392 2.151 40.512 30.249 ;
        RECT  37.692 2.151 37.812 30.249 ;
        RECT  34.992 2.151 35.112 30.249 ;
        RECT  32.292 2.151 32.412 30.249 ;
        RECT  29.592 2.151 29.712 30.249 ;
        RECT  26.892 2.151 27.012 30.249 ;
        RECT  24.192 2.151 24.312 30.249 ;
        RECT  21.492 2.151 21.612 30.249 ;
        RECT  18.792 2.151 18.912 30.249 ;
        RECT  16.092 2.151 16.212 30.249 ;
        RECT  13.392 2.151 13.512 30.249 ;
        RECT  10.692 2.151 10.812 30.249 ;
        RECT  7.992 2.151 8.112 30.249 ;
        RECT  5.292 2.151 5.412 30.249 ;
        RECT  2.592 2.151 2.712 30.249 ;
    END
  END VDD
  PIN VSS
    DIRECTION INOUT ;
    USE GROUND ;
    PORT
      LAYER M5 ;
        RECT  40.2 2.137 40.32 30.263 ;
        RECT  37.5 2.137 37.62 30.263 ;
        RECT  34.8 2.137 34.92 30.263 ;
        RECT  32.1 2.137 32.22 30.263 ;
        RECT  29.4 2.137 29.52 30.263 ;
        RECT  26.7 2.137 26.82 30.263 ;
        RECT  24 2.137 24.12 30.263 ;
        RECT  21.3 2.137 21.42 30.263 ;
        RECT  18.6 2.137 18.72 30.263 ;
        RECT  15.9 2.137 16.02 30.263 ;
        RECT  13.2 2.137 13.32 30.263 ;
        RECT  10.5 2.137 10.62 30.263 ;
        RECT  7.8 2.137 7.92 30.263 ;
        RECT  5.1 2.137 5.22 30.263 ;
        RECT  2.4 2.137 2.52 30.263 ;
    END
  END VSS
  # OT_OBS_CLOSED layer=M5 d_um=1.536 added=98
  OBS
    LAYER RVTN ;
     RECT  2.16 2.16 41.04 2.295 ;
     RECT  2.16 2.565 41.04 2.835 ;
     RECT  2.16 3.105 41.04 3.375 ;
     RECT  2.16 3.645 41.04 3.915 ;
     RECT  2.16 4.185 41.04 4.455 ;
     RECT  2.16 4.725 41.04 4.995 ;
     RECT  2.16 5.265 41.04 5.535 ;
     RECT  2.16 5.805 41.04 6.075 ;
     RECT  2.16 6.345 41.04 6.615 ;
     RECT  2.16 6.885 41.04 7.155 ;
     RECT  2.16 7.425 41.04 7.695 ;
     RECT  2.16 7.965 41.04 8.235 ;
     RECT  2.16 8.505 41.04 8.775 ;
     RECT  2.16 9.045 41.04 9.315 ;
     RECT  2.16 9.585 41.04 9.855 ;
     RECT  2.16 10.125 41.04 10.395 ;
     RECT  2.16 10.665 41.04 10.935 ;
     RECT  2.16 11.205 41.04 11.475 ;
     RECT  2.16 11.745 41.04 12.015 ;
     RECT  2.16 12.285 41.04 12.555 ;
     RECT  2.16 12.825 41.04 13.095 ;
     RECT  2.16 13.365 41.04 13.635 ;
     RECT  2.16 13.905 41.04 14.175 ;
     RECT  2.16 14.445 41.04 14.715 ;
     RECT  2.16 14.985 41.04 15.255 ;
     RECT  2.16 15.525 41.04 15.795 ;
     RECT  2.16 16.065 41.04 16.335 ;
     RECT  2.16 16.605 41.04 16.875 ;
     RECT  2.16 17.145 41.04 17.415 ;
     RECT  2.16 17.685 41.04 17.955 ;
     RECT  2.16 18.225 41.04 18.495 ;
     RECT  2.16 18.765 41.04 19.035 ;
     RECT  2.16 19.305 41.04 19.575 ;
     RECT  2.16 19.845 41.04 20.115 ;
     RECT  2.16 20.385 41.04 20.655 ;
     RECT  2.16 20.925 41.04 21.195 ;
     RECT  2.16 21.465 41.04 21.735 ;
     RECT  2.16 22.005 41.04 22.275 ;
     RECT  2.16 22.545 41.04 22.815 ;
     RECT  2.16 23.085 41.04 23.355 ;
     RECT  2.16 23.625 41.04 23.895 ;
     RECT  2.16 24.165 41.04 24.435 ;
     RECT  2.16 24.705 41.04 24.975 ;
     RECT  2.16 25.245 41.04 25.515 ;
     RECT  2.16 25.785 41.04 26.055 ;
     RECT  2.16 26.325 41.04 26.595 ;
     RECT  2.16 26.865 41.04 27.135 ;
     RECT  2.16 27.405 41.04 27.675 ;
     RECT  2.16 27.945 41.04 28.215 ;
     RECT  2.16 28.485 41.04 28.755 ;
     RECT  2.16 29.025 41.04 29.295 ;
     RECT  2.16 29.565 41.04 29.835 ;
     RECT  2.16 30.105 41.04 30.24 ;
    LAYER RVTP ;
     RECT  2.16 2.295 41.04 2.565 ;
     RECT  2.16 2.835 41.04 3.105 ;
     RECT  2.16 3.375 41.04 3.645 ;
     RECT  2.16 3.915 41.04 4.185 ;
     RECT  2.16 4.455 41.04 4.725 ;
     RECT  2.16 4.995 41.04 5.265 ;
     RECT  2.16 5.535 41.04 5.805 ;
     RECT  2.16 6.075 41.04 6.345 ;
     RECT  2.16 6.615 41.04 6.885 ;
     RECT  2.16 7.155 41.04 7.425 ;
     RECT  2.16 7.695 41.04 7.965 ;
     RECT  2.16 8.235 41.04 8.505 ;
     RECT  2.16 8.775 41.04 9.045 ;
     RECT  2.16 9.315 41.04 9.585 ;
     RECT  2.16 9.855 41.04 10.125 ;
     RECT  2.16 10.395 41.04 10.665 ;
     RECT  2.16 10.935 41.04 11.205 ;
     RECT  2.16 11.475 41.04 11.745 ;
     RECT  2.16 12.015 41.04 12.285 ;
     RECT  2.16 12.555 41.04 12.825 ;
     RECT  2.16 13.095 41.04 13.365 ;
     RECT  2.16 13.635 41.04 13.905 ;
     RECT  2.16 14.175 41.04 14.445 ;
     RECT  2.16 14.715 41.04 14.985 ;
     RECT  2.16 15.255 41.04 15.525 ;
     RECT  2.16 15.795 41.04 16.065 ;
     RECT  2.16 16.335 41.04 16.605 ;
     RECT  2.16 16.875 41.04 17.145 ;
     RECT  2.16 17.415 41.04 17.685 ;
     RECT  2.16 17.955 41.04 18.225 ;
     RECT  2.16 18.495 41.04 18.765 ;
     RECT  2.16 19.035 41.04 19.305 ;
     RECT  2.16 19.575 41.04 19.845 ;
     RECT  2.16 20.115 41.04 20.385 ;
     RECT  2.16 20.655 41.04 20.925 ;
     RECT  2.16 21.195 41.04 21.465 ;
     RECT  2.16 21.735 41.04 22.005 ;
     RECT  2.16 22.275 41.04 22.545 ;
     RECT  2.16 22.815 41.04 23.085 ;
     RECT  2.16 23.355 41.04 23.625 ;
     RECT  2.16 23.895 41.04 24.165 ;
     RECT  2.16 24.435 41.04 24.705 ;
     RECT  2.16 24.975 41.04 25.245 ;
     RECT  2.16 25.515 41.04 25.785 ;
     RECT  2.16 26.055 41.04 26.325 ;
     RECT  2.16 26.595 41.04 26.865 ;
     RECT  2.16 27.135 41.04 27.405 ;
     RECT  2.16 27.675 41.04 27.945 ;
     RECT  2.16 28.215 41.04 28.485 ;
     RECT  2.16 28.755 41.04 29.025 ;
     RECT  2.16 29.295 41.04 29.565 ;
     RECT  2.16 29.835 41.04 30.105 ;
    LAYER M1 ;
     RECT  2.16 2.151 41.04 30.249 ;
    LAYER M2 ;
     RECT  0.103 2.646 0.139 2.664 ;
     RECT  0.103 3.771 0.139 3.789 ;
     RECT  0.103 14.796 0.175 14.814 ;
     RECT  0.103 15.768 0.175 17.244 ;
     RECT  0.103 10.251 0.203 10.269 ;
     RECT  0.175 14.796 0.203 17.244 ;
     RECT  0.103 19.116 0.203 19.134 ;
     RECT  0.203 16.11 0.211 17.244 ;
     RECT  0.211 16.11 0.283 17.514 ;
     RECT  0.139 2.646 0.499 4.284 ;
     RECT  0.499 2.646 0.535 4.374 ;
     RECT  0.103 22.176 0.535 22.806 ;
     RECT  0.103 23.904 0.535 23.922 ;
     RECT  0.535 2.646 2.16 4.482 ;
     RECT  0.203 14.796 2.16 15.354 ;
     RECT  0.283 16.11 2.16 17.604 ;
     RECT  0.535 21.906 2.16 23.922 ;
     RECT  2.16 2.151 26.743 30.249 ;
     RECT  26.815 32.346 27.059 32.364 ;
     RECT  26.743 2.151 28.031 30.33 ;
     RECT  28.031 2.151 41.04 30.249 ;
     RECT  41.04 13.95 41.063 17.712 ;
     RECT  41.04 5.814 41.315 12.924 ;
     RECT  41.063 14.22 41.567 17.712 ;
     RECT  41.04 25.02 41.567 29.322 ;
     RECT  41.567 15.768 41.603 17.712 ;
     RECT  41.567 25.758 41.675 29.322 ;
     RECT  41.567 14.22 42.079 14.814 ;
     RECT  41.315 10.98 42.179 12.924 ;
     RECT  41.603 15.768 42.179 15.822 ;
     RECT  42.179 11.52 42.215 12.924 ;
     RECT  41.675 25.83 42.215 29.322 ;
     RECT  41.315 5.814 42.251 9.918 ;
     RECT  42.079 14.184 42.251 14.814 ;
     RECT  42.215 26.334 42.251 27.162 ;
     RECT  42.215 28.188 42.251 29.322 ;
     RECT  42.251 5.814 42.287 5.832 ;
     RECT  42.215 11.52 42.287 12.384 ;
     RECT  42.251 26.334 42.287 26.928 ;
     RECT  42.251 6.966 42.323 8.028 ;
     RECT  41.04 4.968 42.359 5.058 ;
     RECT  41.04 19.116 42.359 22.374 ;
     RECT  42.323 6.966 42.395 7.452 ;
     RECT  42.359 20.394 42.395 22.374 ;
     RECT  42.287 11.52 42.935 11.97 ;
     RECT  42.251 8.82 42.971 9.918 ;
     RECT  41.603 16.65 42.971 17.712 ;
     RECT  42.359 19.116 42.979 19.368 ;
     RECT  42.359 5.04 43.007 5.058 ;
     RECT  42.935 11.52 43.007 11.538 ;
     RECT  42.251 14.76 43.007 14.814 ;
     RECT  42.395 22.356 43.015 22.374 ;
     RECT  42.287 26.91 43.015 26.928 ;
     RECT  42.971 16.65 43.043 17.208 ;
     RECT  42.395 7.056 43.051 7.452 ;
     RECT  43.015 26.91 43.087 27.234 ;
     RECT  42.971 8.856 43.115 9.918 ;
     RECT  43.007 14.796 43.115 14.814 ;
     RECT  42.179 15.804 43.115 15.822 ;
     RECT  43.043 16.65 43.115 17.019 ;
     RECT  42.979 18.81 43.115 19.368 ;
     RECT  42.395 21.51 43.115 21.528 ;
     RECT  43.015 22.356 43.115 22.608 ;
     RECT  43.087 26.721 43.115 27.234 ;
     RECT  42.251 29.304 43.115 29.322 ;
     RECT  43.051 7.056 43.151 7.65 ;
     RECT  43.115 9.522 43.151 9.918 ;
     RECT  43.051 10.836 43.151 10.854 ;
     RECT  42.395 20.394 43.151 20.484 ;
     RECT  41.04 3.348 43.187 3.366 ;
     RECT  43.151 7.056 43.187 7.074 ;
     RECT  43.151 9.522 43.187 9.54 ;
     RECT  43.087 13.374 43.187 13.392 ;
     RECT  43.115 17.001 43.187 17.019 ;
     RECT  43.151 20.394 43.187 20.412 ;
     RECT  43.115 22.356 43.187 22.374 ;
     RECT  43.115 26.721 43.187 26.739 ;
    LAYER M3 ;
     RECT  7.815 2.143 7.905 2.191 ;
     RECT  10.515 2.143 10.605 2.191 ;
     RECT  13.215 2.143 13.305 2.191 ;
     RECT  21.315 2.143 21.405 2.191 ;
     RECT  7.815 2.191 8.406 2.227 ;
     RECT  10.296 2.191 10.605 2.227 ;
     RECT  24.015 2.143 24.105 2.251 ;
     RECT  25.38 2.191 25.398 2.251 ;
     RECT  7.815 2.227 8.514 2.263 ;
     RECT  16.884 2.227 16.902 2.263 ;
     RECT  13.215 2.191 14.022 2.293 ;
     RECT  7.524 2.263 8.514 2.299 ;
     RECT  13.215 2.293 14.058 2.299 ;
     RECT  15.915 2.143 16.005 2.299 ;
     RECT  16.884 2.263 17.118 2.299 ;
     RECT  18.615 2.143 18.705 2.299 ;
     RECT  18.576 2.299 18.705 2.335 ;
     RECT  21.315 2.191 21.762 2.335 ;
     RECT  6.696 2.299 6.714 2.371 ;
     RECT  15.915 2.299 17.118 2.371 ;
     RECT  17.892 2.335 18.705 2.371 ;
     RECT  24.015 2.251 25.398 2.371 ;
     RECT  2.415 2.143 2.505 2.413 ;
     RECT  5.115 2.143 5.205 2.413 ;
     RECT  6.012 2.371 6.714 2.413 ;
     RECT  10.152 2.227 10.605 2.413 ;
     RECT  15.915 2.371 18.705 2.413 ;
     RECT  26.715 2.143 26.805 2.413 ;
     RECT  29.415 2.143 29.505 2.413 ;
     RECT  32.115 2.143 32.205 2.413 ;
     RECT  34.815 2.143 34.905 2.413 ;
     RECT  37.515 2.143 37.605 2.413 ;
     RECT  40.215 2.143 40.305 2.413 ;
     RECT  7.524 2.299 9.234 2.461 ;
     RECT  10.152 2.413 10.797 2.461 ;
     RECT  13.215 2.299 14.31 2.461 ;
     RECT  7.524 2.461 10.797 2.491 ;
     RECT  11.772 2.461 11.79 2.491 ;
     RECT  2.415 2.413 2.697 2.497 ;
     RECT  7.524 2.491 11.79 2.497 ;
     RECT  13.215 2.461 14.598 2.497 ;
     RECT  23.184 2.299 23.202 2.497 ;
     RECT  24.015 2.371 25.794 2.497 ;
     RECT  29.415 2.413 29.697 2.497 ;
     RECT  26.715 2.413 26.997 2.533 ;
     RECT  29.415 2.497 29.862 2.533 ;
     RECT  15.915 2.413 18.897 2.539 ;
     RECT  5.115 2.413 6.714 2.569 ;
     RECT  29.34 2.533 29.862 2.569 ;
     RECT  4.932 2.569 6.714 2.605 ;
     RECT  15.915 2.539 19.17 2.605 ;
     RECT  21.168 2.335 21.762 2.605 ;
     RECT  23.184 2.497 25.794 2.605 ;
     RECT  2.415 2.497 3.15 2.641 ;
     RECT  15.915 2.605 19.314 2.641 ;
     RECT  21.168 2.605 22.014 2.641 ;
     RECT  23.04 2.605 25.794 2.641 ;
     RECT  26.715 2.533 27.846 2.641 ;
     RECT  2.415 2.641 4.05 2.731 ;
     RECT  7.524 2.497 11.898 2.731 ;
     RECT  13.14 2.497 14.598 2.731 ;
     RECT  28.98 2.569 29.862 2.759 ;
     RECT  4.932 2.605 6.786 2.767 ;
     RECT  7.524 2.731 14.598 2.767 ;
     RECT  15.915 2.641 19.386 2.767 ;
     RECT  20.16 2.641 22.014 2.767 ;
     RECT  23.04 2.641 25.866 2.767 ;
     RECT  26.715 2.641 27.918 2.795 ;
     RECT  2.415 2.731 4.122 2.803 ;
     RECT  4.932 2.767 14.598 2.803 ;
     RECT  20.16 2.767 25.866 2.827 ;
     RECT  15.912 2.767 19.386 2.875 ;
     RECT  20.16 2.827 25.938 2.875 ;
     RECT  26.715 2.795 27.882 2.875 ;
     RECT  15.48 2.875 27.882 3.029 ;
     RECT  2.415 2.803 14.598 3.037 ;
     RECT  15.48 3.029 17.334 3.037 ;
     RECT  18.216 3.029 27.882 3.065 ;
     RECT  0.108 2.641 0.126 3.181 ;
     RECT  18.216 3.065 22.194 3.299 ;
     RECT  32.115 2.413 32.397 3.307 ;
     RECT  0.108 3.181 0.234 3.379 ;
     RECT  37.515 2.413 37.797 3.451 ;
     RECT  23.076 3.065 27.882 3.541 ;
     RECT  29.088 2.759 29.862 3.541 ;
     RECT  28.728 3.541 29.862 3.547 ;
     RECT  23.076 3.541 27.918 3.577 ;
     RECT  28.728 3.547 30.582 3.577 ;
     RECT  23.076 3.577 30.582 3.685 ;
     RECT  23.076 3.685 30.726 3.721 ;
     RECT  31.464 3.307 32.397 3.721 ;
     RECT  2.415 3.037 17.334 3.811 ;
     RECT  18.216 3.299 22.086 3.811 ;
     RECT  23.076 3.721 32.397 3.811 ;
     RECT  43.164 3.343 43.182 3.883 ;
     RECT  43.128 3.883 43.182 3.931 ;
     RECT  2.376 3.811 22.086 4.081 ;
     RECT  23.076 3.811 32.742 4.081 ;
     RECT  2.376 4.081 32.742 4.153 ;
     RECT  0.108 3.379 0.558 4.205 ;
     RECT  2.34 4.153 32.742 4.253 ;
     RECT  2.34 4.253 28.278 4.261 ;
     RECT  29.016 4.253 32.742 4.261 ;
     RECT  0.144 4.205 0.558 4.301 ;
     RECT  29.016 4.261 33.138 4.387 ;
     RECT  34.815 2.413 35.097 4.423 ;
     RECT  40.215 2.413 40.497 4.531 ;
     RECT  0.504 4.301 0.558 4.589 ;
     RECT  0.504 4.589 0.522 4.685 ;
     RECT  2.304 4.261 28.278 4.729 ;
     RECT  38.88 3.991 38.898 4.801 ;
     RECT  39.672 4.531 40.497 4.801 ;
     RECT  37.26 3.451 37.797 4.919 ;
     RECT  38.88 4.801 40.497 4.919 ;
     RECT  2.268 4.729 28.278 4.955 ;
     RECT  42.948 3.931 43.182 4.963 ;
     RECT  29.016 4.387 33.282 4.999 ;
     RECT  42.336 4.963 43.182 4.999 ;
     RECT  11.916 4.955 28.278 5.161 ;
     RECT  29.016 4.999 33.642 5.161 ;
     RECT  2.268 4.955 10.797 5.179 ;
     RECT  2.232 5.179 10.797 5.225 ;
     RECT  34.815 4.423 35.37 5.341 ;
     RECT  0.324 5.419 0.342 5.467 ;
     RECT  0.216 5.467 0.342 5.549 ;
     RECT  11.916 5.161 33.642 5.567 ;
     RECT  0.216 5.549 0.234 5.645 ;
     RECT  11.916 5.567 25.074 5.737 ;
     RECT  26.1 5.567 33.642 5.765 ;
     RECT  11.7 5.737 25.074 5.809 ;
     RECT  2.268 5.225 10.797 5.933 ;
     RECT  2.304 5.933 10.797 5.971 ;
     RECT  11.592 5.809 25.074 5.971 ;
     RECT  38.88 4.919 38.898 5.999 ;
     RECT  40.215 4.919 40.497 6.079 ;
     RECT  2.304 5.971 25.074 6.107 ;
     RECT  2.34 6.107 25.074 6.179 ;
     RECT  2.376 6.179 3.762 6.269 ;
     RECT  28.584 5.765 33.642 6.269 ;
     RECT  34.815 5.341 35.802 6.269 ;
     RECT  38.736 6.313 38.754 6.413 ;
     RECT  34.815 6.269 35.694 6.655 ;
     RECT  26.1 5.765 27.738 6.667 ;
     RECT  28.584 6.269 33.498 6.667 ;
     RECT  4.536 6.179 25.074 6.691 ;
     RECT  26.1 6.667 33.498 6.817 ;
     RECT  4.536 6.691 25.218 6.845 ;
     RECT  26.064 6.817 33.498 6.889 ;
     RECT  39.924 6.079 40.497 6.893 ;
     RECT  4.536 6.845 19.386 6.917 ;
     RECT  2.415 6.269 3.762 7.079 ;
     RECT  42.192 4.999 43.182 7.079 ;
     RECT  25.38 6.889 33.498 7.187 ;
     RECT  2.415 7.079 2.862 7.223 ;
     RECT  25.848 7.187 33.498 7.229 ;
     RECT  3.6 7.079 3.762 7.387 ;
     RECT  4.536 6.917 8.694 7.387 ;
     RECT  9.54 6.917 19.386 7.591 ;
     RECT  20.124 6.845 24.606 7.591 ;
     RECT  33.48 7.229 33.498 7.619 ;
     RECT  42.192 7.079 43.146 7.655 ;
     RECT  37.296 4.919 37.797 7.661 ;
     RECT  3.6 7.387 8.694 7.699 ;
     RECT  9.54 7.591 24.606 7.699 ;
     RECT  42.192 7.655 43.074 7.853 ;
     RECT  25.848 7.229 32.67 7.889 ;
     RECT  3.6 7.699 24.606 7.925 ;
     RECT  3.6 7.925 14.418 7.997 ;
     RECT  15.192 7.925 24.606 7.997 ;
     RECT  15.876 7.997 24.606 8.005 ;
     RECT  25.848 7.889 28.494 8.005 ;
     RECT  15.876 8.005 28.494 8.159 ;
     RECT  37.515 7.661 37.797 8.203 ;
     RECT  34.38 6.655 35.694 8.237 ;
     RECT  39.312 8.203 39.33 8.239 ;
     RECT  29.232 7.889 32.67 8.285 ;
     RECT  38.808 8.239 39.33 8.311 ;
     RECT  40.215 6.893 40.497 8.311 ;
     RECT  37.515 8.203 37.89 8.333 ;
     RECT  31.104 8.285 32.67 8.339 ;
     RECT  38.808 8.311 40.59 8.429 ;
     RECT  38.808 8.429 39.438 8.501 ;
     RECT  42.192 7.853 43.002 8.509 ;
     RECT  34.38 8.237 35.097 8.525 ;
     RECT  41.58 8.509 43.002 8.621 ;
     RECT  15.876 8.159 28.242 8.699 ;
     RECT  39.168 8.501 39.438 8.699 ;
     RECT  29.232 8.285 30.33 8.707 ;
     RECT  42.192 8.621 43.002 8.827 ;
     RECT  3.6 7.997 10.89 8.851 ;
     RECT  11.628 7.997 14.418 8.851 ;
     RECT  42.192 8.827 43.038 8.851 ;
     RECT  20.88 8.699 28.242 8.861 ;
     RECT  31.392 8.339 32.67 8.861 ;
     RECT  29.088 8.707 30.33 8.977 ;
     RECT  15.876 8.699 19.818 9.085 ;
     RECT  20.916 8.861 28.242 9.113 ;
     RECT  3.6 8.851 14.418 9.115 ;
     RECT  15.804 9.085 19.818 9.115 ;
     RECT  2.415 7.223 2.697 9.121 ;
     RECT  3.6 9.115 14.634 9.121 ;
     RECT  21.096 9.113 28.242 9.283 ;
     RECT  28.98 8.977 30.33 9.283 ;
     RECT  15.732 9.115 19.818 9.319 ;
     RECT  39.168 8.699 39.186 9.319 ;
     RECT  2.415 9.121 14.634 9.391 ;
     RECT  15.66 9.319 19.818 9.391 ;
     RECT  33.876 9.355 33.894 9.391 ;
     RECT  34.704 8.525 35.097 9.391 ;
     RECT  2.412 9.391 14.634 9.419 ;
     RECT  21.096 9.283 30.33 9.481 ;
     RECT  14.544 9.419 14.634 9.517 ;
     RECT  36.648 9.283 36.666 9.517 ;
     RECT  37.515 8.333 37.797 9.517 ;
     RECT  42.192 8.851 43.11 9.517 ;
     RECT  2.412 9.419 13.497 9.545 ;
     RECT  15.588 9.391 19.818 9.547 ;
     RECT  42.192 9.517 43.182 9.581 ;
     RECT  14.544 9.517 14.778 9.589 ;
     RECT  15.552 9.547 19.818 9.589 ;
     RECT  31.392 8.861 32.397 9.589 ;
     RECT  33.12 9.283 33.138 9.589 ;
     RECT  33.876 9.391 35.097 9.589 ;
     RECT  2.412 9.545 8.154 9.643 ;
     RECT  2.304 9.643 8.154 9.653 ;
     RECT  43.092 9.581 43.182 9.653 ;
     RECT  36.504 9.517 37.797 9.661 ;
     RECT  40.215 8.429 40.497 9.661 ;
     RECT  2.304 9.653 5.958 9.739 ;
     RECT  36.468 9.661 37.797 9.751 ;
     RECT  42.192 9.581 42.282 9.773 ;
     RECT  36.468 9.751 37.854 9.787 ;
     RECT  36.468 9.787 37.998 9.823 ;
     RECT  38.808 9.319 39.186 9.823 ;
     RECT  21.096 9.481 30.402 9.859 ;
     RECT  41.58 9.823 41.598 9.869 ;
     RECT  20.736 9.859 30.402 9.895 ;
     RECT  31.392 9.589 35.097 9.895 ;
     RECT  36.216 9.823 39.186 9.895 ;
     RECT  36 9.895 39.186 10.057 ;
     RECT  9 9.545 13.497 10.085 ;
     RECT  13.104 10.085 13.497 10.201 ;
     RECT  14.544 9.589 19.818 10.219 ;
     RECT  35.928 10.057 39.186 10.219 ;
     RECT  0.144 10.075 0.162 10.246 ;
     RECT  13.104 10.201 13.626 10.253 ;
     RECT  6.804 9.653 8.154 10.291 ;
     RECT  9 10.085 12.366 10.291 ;
     RECT  20.736 9.895 35.097 10.327 ;
     RECT  35.892 10.219 39.186 10.327 ;
     RECT  40.215 9.661 40.626 10.327 ;
     RECT  0.108 10.246 0.198 10.349 ;
     RECT  20.736 10.327 40.626 10.363 ;
     RECT  0.144 10.349 0.198 10.397 ;
     RECT  2.268 9.739 5.958 10.435 ;
     RECT  6.804 10.291 12.366 10.435 ;
     RECT  20.736 10.363 41.31 10.463 ;
     RECT  14.472 10.219 19.818 10.471 ;
     RECT  20.736 10.463 29.697 10.471 ;
     RECT  14.472 10.471 29.697 10.696 ;
     RECT  2.268 10.435 12.366 10.769 ;
     RECT  30.672 10.463 41.31 10.781 ;
     RECT  43.128 9.653 43.182 10.831 ;
     RECT  14.436 10.696 29.697 10.859 ;
     RECT  2.304 10.769 12.366 10.867 ;
     RECT  13.104 10.253 13.497 10.867 ;
     RECT  14.436 10.859 22.158 10.877 ;
     RECT  2.304 10.867 13.497 10.975 ;
     RECT  14.436 10.877 22.086 10.975 ;
     RECT  23.076 10.859 29.697 11.003 ;
     RECT  23.148 11.003 29.697 11.281 ;
     RECT  30.672 10.781 30.87 11.281 ;
     RECT  0.144 10.397 0.162 11.309 ;
     RECT  23.148 11.281 30.87 11.506 ;
     RECT  43.056 10.831 43.182 11.515 ;
     RECT  2.304 10.975 22.086 11.741 ;
     RECT  15.3 11.741 22.086 11.749 ;
     RECT  31.68 10.781 41.31 11.777 ;
     RECT  23.148 11.506 30.906 11.821 ;
     RECT  31.68 11.777 36.774 11.821 ;
     RECT  37.515 11.777 41.31 11.821 ;
     RECT  42.156 10.975 42.174 11.821 ;
     RECT  15.3 11.749 22.122 11.899 ;
     RECT  23.148 11.821 36.774 11.899 ;
     RECT  15.3 11.899 36.774 11.939 ;
     RECT  42.984 11.515 43.182 11.947 ;
     RECT  37.515 11.821 42.174 12.361 ;
     RECT  42.912 11.947 43.182 12.361 ;
     RECT  15.3 11.939 30.942 12.365 ;
     RECT  28.224 12.365 30.942 12.389 ;
     RECT  2.304 11.741 14.166 12.557 ;
     RECT  2.415 12.557 14.166 12.595 ;
     RECT  15.3 12.365 27.45 12.595 ;
     RECT  28.98 12.389 30.942 12.721 ;
     RECT  31.716 11.939 36.774 12.721 ;
     RECT  28.98 12.721 36.774 12.865 ;
     RECT  37.515 12.361 43.182 12.865 ;
     RECT  2.415 12.595 27.45 13.055 ;
     RECT  7.236 13.055 27.45 13.261 ;
     RECT  28.224 12.389 28.242 13.261 ;
     RECT  7.236 13.261 28.242 13.325 ;
     RECT  28.98 12.865 43.182 13.325 ;
     RECT  40.176 13.325 43.182 13.397 ;
     RECT  40.176 13.397 43.11 13.421 ;
     RECT  2.415 13.055 6.426 13.433 ;
     RECT  15.3 13.325 28.242 13.435 ;
     RECT  28.98 13.325 39.402 13.435 ;
     RECT  7.236 13.325 14.562 13.469 ;
     RECT  3.888 13.433 6.426 13.559 ;
     RECT  7.236 13.469 14.49 13.559 ;
     RECT  7.236 13.559 14.454 13.595 ;
     RECT  15.3 13.435 39.402 13.595 ;
     RECT  9.864 13.595 14.454 13.631 ;
     RECT  21.096 13.595 39.402 13.661 ;
     RECT  21.096 13.661 31.158 13.667 ;
     RECT  40.176 13.421 43.074 13.805 ;
     RECT  4.176 13.559 6.426 13.873 ;
     RECT  7.236 13.595 8.874 13.873 ;
     RECT  40.176 13.805 43.038 13.997 ;
     RECT  15.3 13.595 20.322 14.135 ;
     RECT  21.096 13.667 31.086 14.171 ;
     RECT  26.172 14.171 31.086 14.237 ;
     RECT  9.864 13.631 14.238 14.369 ;
     RECT  32.04 13.661 39.402 14.429 ;
     RECT  4.176 13.873 8.874 14.449 ;
     RECT  26.316 14.237 31.086 14.525 ;
     RECT  4.176 14.449 8.91 14.635 ;
     RECT  21.096 14.171 25.11 14.635 ;
     RECT  15.696 14.135 20.322 14.639 ;
     RECT  21.06 14.635 25.11 14.639 ;
     RECT  15.696 14.639 20.178 14.675 ;
     RECT  9.864 14.369 12.222 14.683 ;
     RECT  40.176 13.997 43.002 14.731 ;
     RECT  4.14 14.635 8.91 14.755 ;
     RECT  13.215 14.369 14.238 14.755 ;
     RECT  26.388 14.525 31.086 14.755 ;
     RECT  32.04 14.429 38.79 14.755 ;
     RECT  21.06 14.639 25.074 14.783 ;
     RECT  40.176 14.731 43.11 14.819 ;
     RECT  13.215 14.755 14.382 14.872 ;
     RECT  15.696 14.675 19.818 14.909 ;
     RECT  3.492 14.755 8.91 14.917 ;
     RECT  3.42 14.917 8.91 14.989 ;
     RECT  13.215 14.872 14.814 14.989 ;
     RECT  0.108 14.791 0.126 15.061 ;
     RECT  40.176 14.819 43.038 15.061 ;
     RECT  39.96 15.061 43.038 15.149 ;
     RECT  3.42 14.989 9.018 15.151 ;
     RECT  9.792 14.683 12.222 15.151 ;
     RECT  3.42 15.151 12.258 15.187 ;
     RECT  13.215 14.989 14.922 15.187 ;
     RECT  26.388 14.755 38.79 15.223 ;
     RECT  15.696 14.909 17.55 15.251 ;
     RECT  2.415 13.433 2.697 15.295 ;
     RECT  3.42 15.187 14.922 15.295 ;
     RECT  18.504 14.909 19.818 15.323 ;
     RECT  26.388 15.223 39.114 15.331 ;
     RECT  26.388 15.331 39.15 15.451 ;
     RECT  26.136 15.451 39.15 15.491 ;
     RECT  2.415 15.295 14.922 15.529 ;
     RECT  43.02 15.149 43.038 15.533 ;
     RECT  2.304 15.529 14.958 15.581 ;
     RECT  2.304 15.581 14.886 15.593 ;
     RECT  15.696 15.251 16.326 15.691 ;
     RECT  17.1 15.251 17.55 15.691 ;
     RECT  18.504 15.323 19.602 15.691 ;
     RECT  28.944 15.491 39.15 15.691 ;
     RECT  39.96 15.149 42.282 15.691 ;
     RECT  26.136 15.491 28.098 15.755 ;
     RECT  43.092 15.691 43.11 15.827 ;
     RECT  28.944 15.691 42.282 15.917 ;
     RECT  26.136 15.755 27.414 15.961 ;
     RECT  17.1 15.691 19.602 15.989 ;
     RECT  15.624 15.691 16.326 16.105 ;
     RECT  17.1 15.989 19.422 16.105 ;
     RECT  21.204 14.783 25.074 16.123 ;
     RECT  26.028 15.961 27.414 16.231 ;
     RECT  28.944 15.917 41.598 16.231 ;
     RECT  28.512 16.231 41.598 16.259 ;
     RECT  21.096 16.123 25.074 16.411 ;
     RECT  25.92 16.231 27.414 16.411 ;
     RECT  2.304 15.593 14.85 16.439 ;
     RECT  40.176 16.259 41.598 16.493 ;
     RECT  40.176 16.493 40.59 16.529 ;
     RECT  20.628 16.411 27.414 16.537 ;
     RECT  28.512 16.259 39.258 16.537 ;
     RECT  0.108 15.061 0.558 16.589 ;
     RECT  41.58 16.493 41.598 16.601 ;
     RECT  20.628 16.537 39.258 16.637 ;
     RECT  43.092 16.645 43.11 16.651 ;
     RECT  39.132 16.637 39.258 16.673 ;
     RECT  2.376 16.439 14.85 16.771 ;
     RECT  15.624 16.105 19.422 16.771 ;
     RECT  20.628 16.637 38.358 16.795 ;
     RECT  2.376 16.771 19.602 16.799 ;
     RECT  2.412 16.799 19.602 16.843 ;
     RECT  20.412 16.795 38.358 16.843 ;
     RECT  2.412 16.843 38.358 16.925 ;
     RECT  40.215 16.529 40.59 16.973 ;
     RECT  21.315 16.925 38.358 16.979 ;
     RECT  42.804 16.651 43.11 16.996 ;
     RECT  25.92 16.979 38.358 17.105 ;
     RECT  25.92 17.105 35.097 17.141 ;
     RECT  0.108 16.589 0.198 17.261 ;
     RECT  0.144 17.261 0.198 17.323 ;
     RECT  21.315 16.979 25.182 17.339 ;
     RECT  1.188 17.419 1.206 17.455 ;
     RECT  35.892 17.105 38.358 17.455 ;
     RECT  39.24 16.673 39.258 17.455 ;
     RECT  40.215 16.973 40.497 17.455 ;
     RECT  1.188 17.455 1.278 17.483 ;
     RECT  1.26 17.483 1.278 17.501 ;
     RECT  25.92 17.141 27.414 17.519 ;
     RECT  25.92 17.519 27.162 17.609 ;
     RECT  28.188 17.141 35.097 17.609 ;
     RECT  35.892 17.455 40.497 17.609 ;
     RECT  0.144 17.323 0.342 17.645 ;
     RECT  2.412 16.925 20.43 17.659 ;
     RECT  25.92 17.609 27.126 17.717 ;
     RECT  2.412 17.659 20.502 17.803 ;
     RECT  25.92 17.717 27.09 17.879 ;
     RECT  2.304 17.803 20.502 17.923 ;
     RECT  21.315 17.339 25.11 17.923 ;
     RECT  0.144 17.645 0.306 17.933 ;
     RECT  28.368 17.609 35.097 18.031 ;
     RECT  35.892 17.609 38.502 18.031 ;
     RECT  2.304 17.923 25.11 18.121 ;
     RECT  25.92 17.879 27.054 18.121 ;
     RECT  2.304 18.121 27.054 18.185 ;
     RECT  21.096 18.185 27.054 18.419 ;
     RECT  28.368 18.031 38.502 18.455 ;
     RECT  28.368 18.455 38.07 18.499 ;
     RECT  21.315 18.419 27.054 18.527 ;
     RECT  21.315 18.527 21.69 18.563 ;
     RECT  22.464 18.527 27.054 18.697 ;
     RECT  28.332 18.499 38.07 18.697 ;
     RECT  22.464 18.697 27.09 18.733 ;
     RECT  28.008 18.697 38.07 18.733 ;
     RECT  22.464 18.733 38.07 18.749 ;
     RECT  0.144 17.933 0.162 18.811 ;
     RECT  0.144 18.811 0.198 18.859 ;
     RECT  39.24 17.609 40.497 19.111 ;
     RECT  42.804 16.996 43.182 19.111 ;
     RECT  0.108 18.859 0.198 19.148 ;
     RECT  38.808 19.111 40.497 19.273 ;
     RECT  42.264 19.111 43.182 19.309 ;
     RECT  0.144 19.148 0.162 19.325 ;
     RECT  21.315 18.563 21.597 19.336 ;
     RECT  2.304 18.185 20.034 19.337 ;
     RECT  2.34 19.337 20.034 19.345 ;
     RECT  21.096 19.336 21.597 19.345 ;
     RECT  22.464 18.749 31.374 19.345 ;
     RECT  2.34 19.345 21.597 19.373 ;
     RECT  20.52 19.373 21.597 19.381 ;
     RECT  22.392 19.345 31.374 19.381 ;
     RECT  42.228 19.309 43.182 19.381 ;
     RECT  2.34 19.373 19.782 19.409 ;
     RECT  20.52 19.381 31.374 19.531 ;
     RECT  32.115 18.749 38.07 19.531 ;
     RECT  20.52 19.531 38.07 19.579 ;
     RECT  38.808 19.273 41.058 19.579 ;
     RECT  20.52 19.579 41.058 19.607 ;
     RECT  42.192 19.381 43.182 19.615 ;
     RECT  20.7 19.607 41.058 19.643 ;
     RECT  2.415 19.409 19.782 19.679 ;
     RECT  23.976 19.643 41.058 19.853 ;
     RECT  23.976 19.853 35.802 19.913 ;
     RECT  2.415 19.679 10.797 20.039 ;
     RECT  34.668 19.913 35.802 20.237 ;
     RECT  23.976 19.913 33.93 20.345 ;
     RECT  42.156 19.615 43.182 20.417 ;
     RECT  3.42 20.039 10.797 20.429 ;
     RECT  11.52 19.679 19.782 20.429 ;
     RECT  3.42 20.429 8.91 20.453 ;
     RECT  9.648 20.429 10.797 20.453 ;
     RECT  31.5 20.345 33.93 20.453 ;
     RECT  42.156 20.417 43.146 20.489 ;
     RECT  20.7 19.643 23.238 20.551 ;
     RECT  23.976 20.345 30.762 20.551 ;
     RECT  3.42 20.453 8.838 20.579 ;
     RECT  36.828 19.853 41.058 20.579 ;
     RECT  20.628 20.551 30.762 20.587 ;
     RECT  12.132 20.429 19.782 20.623 ;
     RECT  20.52 20.587 30.762 20.623 ;
     RECT  36.828 20.579 39.366 20.759 ;
     RECT  32.076 20.453 33.93 20.849 ;
     RECT  36.828 20.759 39.186 20.849 ;
     RECT  40.215 20.579 41.058 20.893 ;
     RECT  42.156 20.489 43.11 20.893 ;
     RECT  36.828 20.849 38.826 20.923 ;
     RECT  36.612 20.923 38.826 20.957 ;
     RECT  36.612 20.957 38.214 21.029 ;
     RECT  9.684 20.453 10.797 21.091 ;
     RECT  3.42 20.579 8.658 21.155 ;
     RECT  9.684 21.091 11.214 21.235 ;
     RECT  34.74 20.237 35.802 21.235 ;
     RECT  34.704 21.235 35.802 21.259 ;
     RECT  36.612 21.029 38.07 21.259 ;
     RECT  40.215 20.893 43.11 21.293 ;
     RECT  9.684 21.235 11.394 21.361 ;
     RECT  34.704 21.259 38.07 21.389 ;
     RECT  34.704 21.389 35.73 21.403 ;
     RECT  8.964 21.361 11.394 21.433 ;
     RECT  12.132 20.623 30.762 21.433 ;
     RECT  41.616 21.293 43.11 21.533 ;
     RECT  3.42 21.155 8.154 21.569 ;
     RECT  8.964 21.433 31.302 21.631 ;
     RECT  40.215 21.293 40.554 21.677 ;
     RECT  3.78 21.569 8.154 21.901 ;
     RECT  8.964 21.631 31.338 21.901 ;
     RECT  32.076 20.849 33.894 21.901 ;
     RECT  34.632 21.403 35.73 21.901 ;
     RECT  36.468 21.389 38.07 21.979 ;
     RECT  41.616 21.533 43.038 22.061 ;
     RECT  3.78 21.901 31.338 22.073 ;
     RECT  2.415 20.039 2.697 22.081 ;
     RECT  36.468 21.979 38.682 22.082 ;
     RECT  42.192 22.061 43.038 22.157 ;
     RECT  0.54 21.901 0.558 22.171 ;
     RECT  32.076 21.901 35.73 22.171 ;
     RECT  36.468 22.082 38.646 22.171 ;
     RECT  31.932 22.171 38.646 22.199 ;
     RECT  31.932 22.199 38.574 22.235 ;
     RECT  2.415 22.081 2.97 22.351 ;
     RECT  3.78 22.073 30.978 22.351 ;
     RECT  42.264 22.157 43.038 22.351 ;
     RECT  2.415 22.351 30.978 22.505 ;
     RECT  0.108 22.171 0.558 22.507 ;
     RECT  2.415 22.505 29.97 22.541 ;
     RECT  42.264 22.351 43.182 22.541 ;
     RECT  31.932 22.235 37.998 22.613 ;
     RECT  0.108 22.507 1.17 22.621 ;
     RECT  37.044 22.613 37.998 22.649 ;
     RECT  42.336 22.541 43.182 22.733 ;
     RECT  0.108 22.621 1.206 22.739 ;
     RECT  31.932 22.613 36.27 22.739 ;
     RECT  37.08 22.649 37.998 22.739 ;
     RECT  2.415 22.541 25.758 22.775 ;
     RECT  2.415 22.775 19.674 22.811 ;
     RECT  31.932 22.739 33.138 22.811 ;
     RECT  20.448 22.775 25.758 22.829 ;
     RECT  42.336 22.733 42.39 22.829 ;
     RECT  2.415 22.811 19.422 22.847 ;
     RECT  30.744 22.505 30.978 22.855 ;
     RECT  31.932 22.811 33.066 22.855 ;
     RECT  0.108 22.739 0.558 22.925 ;
     RECT  42.372 22.829 42.39 22.925 ;
     RECT  33.876 22.739 36.27 23.117 ;
     RECT  37.116 22.739 37.998 23.125 ;
     RECT  26.568 22.541 29.97 23.315 ;
     RECT  26.715 23.315 29.97 23.323 ;
     RECT  30.744 22.855 33.066 23.323 ;
     RECT  26.715 23.323 33.066 23.557 ;
     RECT  33.876 23.117 36.162 23.557 ;
     RECT  2.415 22.847 11.718 23.593 ;
     RECT  12.456 22.847 19.422 23.593 ;
     RECT  20.736 22.829 25.758 23.593 ;
     RECT  20.16 23.593 25.758 23.657 ;
     RECT  2.415 23.593 19.422 23.659 ;
     RECT  0.144 22.925 0.558 23.851 ;
     RECT  0.144 23.851 0.594 23.863 ;
     RECT  0.144 23.863 0.666 23.899 ;
     RECT  2.304 23.659 19.422 23.971 ;
     RECT  20.16 23.657 25.686 23.971 ;
     RECT  0.108 23.899 0.666 23.981 ;
     RECT  0.108 23.981 0.162 24.077 ;
     RECT  26.715 23.557 36.162 24.089 ;
     RECT  2.304 23.971 25.686 24.125 ;
     RECT  37.116 23.125 38.322 24.205 ;
     RECT  40.215 21.677 40.497 24.205 ;
     RECT  37.008 24.205 38.322 24.359 ;
     RECT  37.008 24.359 37.998 24.467 ;
     RECT  37.008 24.467 37.89 24.503 ;
     RECT  37.008 24.503 37.797 24.509 ;
     RECT  2.304 24.125 25.65 24.539 ;
     RECT  26.715 24.089 34.038 24.629 ;
     RECT  0.144 24.077 0.162 24.701 ;
     RECT  29.052 24.629 34.038 24.899 ;
     RECT  40.215 24.205 40.842 24.899 ;
     RECT  29.052 24.899 33.102 24.935 ;
     RECT  0.324 24.811 0.342 24.941 ;
     RECT  1.152 24.091 1.17 25.085 ;
     RECT  29.304 24.935 33.102 25.085 ;
     RECT  2.304 24.539 25.614 25.169 ;
     RECT  34.776 24.089 36.162 25.169 ;
     RECT  29.304 25.085 32.598 25.277 ;
     RECT  17.424 25.169 25.614 25.321 ;
     RECT  26.715 24.629 28.206 25.321 ;
     RECT  2.304 25.169 16.614 25.349 ;
     RECT  29.304 25.277 32.526 25.349 ;
     RECT  34.815 25.169 36.162 25.439 ;
     RECT  17.424 25.321 28.206 25.447 ;
     RECT  39.096 24.745 39.114 25.519 ;
     RECT  17.424 25.447 28.242 25.531 ;
     RECT  34.815 25.439 36.09 25.583 ;
     RECT  40.215 24.899 40.698 25.591 ;
     RECT  34.815 25.583 36.018 25.619 ;
     RECT  38.916 25.519 39.114 25.709 ;
     RECT  17.424 25.531 28.35 25.745 ;
     RECT  41.544 25.015 41.562 25.753 ;
     RECT  12.384 25.349 16.614 25.817 ;
     RECT  41.544 25.753 41.67 25.825 ;
     RECT  40.068 25.591 40.698 25.861 ;
     RECT  12.384 25.817 16.542 25.979 ;
     RECT  17.604 25.745 28.35 25.979 ;
     RECT  39.78 25.861 40.698 25.979 ;
     RECT  12.384 25.979 16.434 26.015 ;
     RECT  2.304 25.349 11.646 26.051 ;
     RECT  41.544 25.825 42.21 26.095 ;
     RECT  17.604 25.979 28.314 26.159 ;
     RECT  3.708 26.051 11.646 26.221 ;
     RECT  12.384 26.015 16.398 26.221 ;
     RECT  41.508 26.095 42.21 26.329 ;
     RECT  17.604 26.159 28.026 26.333 ;
     RECT  35.928 25.619 35.946 26.381 ;
     RECT  2.304 26.051 2.754 26.429 ;
     RECT  43.164 22.733 43.182 26.587 ;
     RECT  29.304 25.349 32.454 26.599 ;
     RECT  17.604 26.333 27.954 26.635 ;
     RECT  29.304 26.599 32.49 26.635 ;
     RECT  40.215 25.979 40.698 26.671 ;
     RECT  41.508 26.329 42.282 26.671 ;
     RECT  29.304 26.635 32.598 26.699 ;
     RECT  17.388 26.635 27.954 26.717 ;
     RECT  40.215 26.671 42.282 26.744 ;
     RECT  43.02 26.587 43.182 26.744 ;
     RECT  3.708 26.221 16.398 26.761 ;
     RECT  17.532 26.717 27.954 26.765 ;
     RECT  38.916 25.709 39.042 26.789 ;
     RECT  3.708 26.761 16.506 26.869 ;
     RECT  40.215 26.744 40.842 26.869 ;
     RECT  38.916 26.789 38.934 26.897 ;
     RECT  38.808 26.905 38.826 26.941 ;
     RECT  29.304 26.699 32.526 27.067 ;
     RECT  38.772 26.941 38.826 27.131 ;
     RECT  29.16 27.067 32.526 27.139 ;
     RECT  2.415 26.429 2.754 27.163 ;
     RECT  3.528 26.869 16.542 27.163 ;
     RECT  34.815 25.619 35.097 27.175 ;
     RECT  2.415 27.163 16.542 27.203 ;
     RECT  29.016 27.139 32.526 27.239 ;
     RECT  43.02 26.744 43.11 27.239 ;
     RECT  9.648 27.203 16.542 27.245 ;
     RECT  43.092 27.239 43.11 27.248 ;
     RECT  34.776 27.175 35.097 27.329 ;
     RECT  9.648 27.245 11.502 27.401 ;
     RECT  17.784 26.765 27.954 27.409 ;
     RECT  17.784 27.409 28.17 27.445 ;
     RECT  29.016 27.239 32.397 27.445 ;
     RECT  12.384 27.245 16.542 27.481 ;
     RECT  40.068 26.869 40.842 27.481 ;
     RECT  17.784 27.445 32.397 27.571 ;
     RECT  17.748 27.571 32.397 27.595 ;
     RECT  12.384 27.481 16.722 27.599 ;
     RECT  17.568 27.595 32.397 27.635 ;
     RECT  41.616 26.744 42.282 27.691 ;
     RECT  39.924 27.481 40.842 27.715 ;
     RECT  41.58 27.691 42.282 27.715 ;
     RECT  39.924 27.715 42.282 27.821 ;
     RECT  39.924 27.821 40.842 27.841 ;
     RECT  41.58 27.821 42.282 27.917 ;
     RECT  3.528 27.203 8.838 27.949 ;
     RECT  9.648 27.401 9.666 27.949 ;
     RECT  39.852 27.841 40.842 27.977 ;
     RECT  10.404 27.401 11.502 27.985 ;
     RECT  3.528 27.949 9.666 28.021 ;
     RECT  17.676 27.635 32.397 28.049 ;
     RECT  2.415 27.203 2.697 28.123 ;
     RECT  3.42 28.021 9.666 28.123 ;
     RECT  2.415 28.123 9.666 28.139 ;
     RECT  17.676 28.049 31.374 28.139 ;
     RECT  6.444 28.139 9.666 28.147 ;
     RECT  10.404 27.985 11.538 28.147 ;
     RECT  17.676 28.139 31.266 28.247 ;
     RECT  6.444 28.147 11.538 28.255 ;
     RECT  12.384 27.599 16.65 28.255 ;
     RECT  17.676 28.247 31.158 28.381 ;
     RECT  2.415 28.139 5.526 28.409 ;
     RECT  17.64 28.381 31.158 28.409 ;
     RECT  6.444 28.255 16.65 28.451 ;
     RECT  17.64 28.409 29.934 28.453 ;
     RECT  17.568 28.453 29.934 28.481 ;
     RECT  6.444 28.451 16.398 28.493 ;
     RECT  41.58 27.917 42.246 28.493 ;
     RECT  29.16 28.481 29.934 28.553 ;
     RECT  38.88 27.751 38.898 28.561 ;
     RECT  38.88 28.561 39.258 28.679 ;
     RECT  40.215 27.977 40.842 28.679 ;
     RECT  10.296 28.493 16.398 28.715 ;
     RECT  6.444 28.493 9.198 28.787 ;
     RECT  7.596 28.787 9.198 28.823 ;
     RECT  17.568 28.481 28.35 28.823 ;
     RECT  34.815 27.329 35.097 28.831 ;
     RECT  3.888 28.409 5.526 28.859 ;
     RECT  41.616 28.493 42.246 28.877 ;
     RECT  17.568 28.823 19.134 28.939 ;
     RECT  3.888 28.859 5.49 28.949 ;
     RECT  7.596 28.823 8.838 28.949 ;
     RECT  10.368 28.715 16.398 28.949 ;
     RECT  17.532 28.939 19.134 28.949 ;
     RECT  34.776 28.831 35.097 28.949 ;
     RECT  6.444 28.787 6.606 28.985 ;
     RECT  10.368 28.949 16.326 28.985 ;
     RECT  6.588 28.985 6.606 29.021 ;
     RECT  14.832 28.985 16.326 29.021 ;
     RECT  7.815 28.949 8.838 29.057 ;
     RECT  10.368 28.985 11.178 29.057 ;
     RECT  11.988 28.985 13.986 29.057 ;
     RECT  14.904 29.021 16.326 29.057 ;
     RECT  17.532 28.949 19.062 29.057 ;
     RECT  7.815 29.057 8.766 29.062 ;
     RECT  41.616 28.877 41.634 29.069 ;
     RECT  7.815 29.062 8.73 29.129 ;
     RECT  3.888 28.949 5.454 29.179 ;
     RECT  7.815 29.129 8.586 29.219 ;
     RECT  19.872 28.823 28.35 29.219 ;
     RECT  38.772 28.831 38.79 29.219 ;
     RECT  7.815 29.219 8.406 29.255 ;
     RECT  10.515 29.057 11.178 29.255 ;
     RECT  11.988 29.057 12.042 29.255 ;
     RECT  43.092 28.939 43.11 29.327 ;
     RECT  10.515 29.255 10.89 29.399 ;
     RECT  11.988 29.255 12.006 29.399 ;
     RECT  13.104 29.057 13.986 29.399 ;
     RECT  3.6 29.179 5.454 29.489 ;
     RECT  17.676 29.057 19.062 29.489 ;
     RECT  19.872 29.219 24.297 29.489 ;
     RECT  30.744 28.409 31.158 29.489 ;
     RECT  3.6 29.489 3.618 29.525 ;
     RECT  4.68 29.489 5.454 29.525 ;
     RECT  5.115 29.525 5.454 29.633 ;
     RECT  20.016 29.489 21.597 29.633 ;
     RECT  31.14 29.489 31.158 29.633 ;
     RECT  20.016 29.633 20.178 29.759 ;
     RECT  20.952 29.633 21.597 29.759 ;
     RECT  25.092 29.219 28.026 29.759 ;
     RECT  29.415 28.553 29.934 29.759 ;
     RECT  13.176 29.399 13.986 29.789 ;
     RECT  14.904 29.057 16.29 29.789 ;
     RECT  17.676 29.489 19.026 29.795 ;
     RECT  15.048 29.789 16.29 29.875 ;
     RECT  2.415 28.409 2.697 29.987 ;
     RECT  5.115 29.633 5.397 29.987 ;
     RECT  7.815 29.255 8.097 29.987 ;
     RECT  10.515 29.399 10.797 29.987 ;
     RECT  21.096 29.759 21.597 29.987 ;
     RECT  22.392 29.489 24.297 29.987 ;
     RECT  29.415 29.759 29.697 29.987 ;
     RECT  32.115 28.049 32.397 29.987 ;
     RECT  34.815 28.949 35.097 29.987 ;
     RECT  37.515 24.509 37.797 29.987 ;
     RECT  40.215 28.679 40.497 29.987 ;
     RECT  13.215 29.789 13.986 30.029 ;
     RECT  15.048 29.875 16.398 30.029 ;
     RECT  18 29.795 19.026 30.029 ;
     RECT  22.392 29.987 24.105 30.029 ;
     RECT  25.092 29.759 25.146 30.029 ;
     RECT  25.92 29.759 28.026 30.029 ;
     RECT  13.215 30.029 13.914 30.065 ;
     RECT  22.392 30.029 22.662 30.065 ;
     RECT  18 30.029 18.705 30.137 ;
     RECT  21.096 29.987 21.405 30.137 ;
     RECT  20.016 29.759 20.034 30.173 ;
     RECT  22.392 30.065 22.41 30.173 ;
     RECT  25.092 30.029 25.11 30.173 ;
     RECT  25.92 30.029 27.054 30.173 ;
     RECT  2.415 29.987 2.505 30.257 ;
     RECT  5.115 29.987 5.205 30.257 ;
     RECT  7.815 29.987 7.905 30.257 ;
     RECT  10.515 29.987 10.605 30.257 ;
     RECT  13.215 30.065 13.305 30.257 ;
     RECT  15.915 30.029 16.005 30.257 ;
     RECT  18.615 30.137 18.705 30.257 ;
     RECT  21.315 30.137 21.405 30.257 ;
     RECT  24.015 30.029 24.105 30.257 ;
     RECT  29.415 29.987 29.505 30.257 ;
     RECT  32.115 29.987 32.205 30.257 ;
     RECT  34.815 29.987 34.905 30.257 ;
     RECT  37.515 29.987 37.605 30.257 ;
     RECT  40.215 29.987 40.305 30.257 ;
     RECT  28.008 30.029 28.026 30.335 ;
     RECT  26.604 30.173 27.054 32.251 ;
     RECT  26.532 32.251 27.054 32.363 ;
     RECT  26.55 32.363 26.604 32.369 ;
     RECT  26.622 32.363 26.676 32.369 ;
     RECT  26.694 32.363 26.748 32.369 ;
     RECT  26.766 32.363 26.82 32.369 ;
     RECT  26.838 32.363 26.892 32.369 ;
     RECT  26.91 32.363 27.054 32.369 ;
     RECT  26.55 32.369 26.604 32.381 ;
     RECT  26.622 32.369 26.676 32.381 ;
     RECT  26.694 32.369 26.748 32.381 ;
     RECT  26.766 32.369 26.82 32.381 ;
     RECT  26.838 32.369 26.892 32.381 ;
    LAYER M4 ;
     RECT  0.084 22.512 0.137 22.536 ;
     RECT  0.06 22.536 0.137 22.608 ;
     RECT  0.084 22.608 0.137 22.632 ;
     RECT  0.06 22.632 0.137 22.704 ;
     RECT  0.084 22.704 0.137 22.728 ;
     RECT  0.06 22.728 0.137 22.8 ;
     RECT  0.084 22.8 0.137 22.824 ;
     RECT  0.06 22.824 0.137 22.896 ;
     RECT  0.084 22.896 0.137 22.92 ;
     RECT  0.06 22.92 0.137 22.992 ;
     RECT  0.084 22.992 0.137 23.016 ;
     RECT  0.06 23.016 0.137 23.088 ;
     RECT  0.084 23.088 0.137 23.112 ;
     RECT  0.06 23.112 0.137 23.184 ;
     RECT  0.084 23.184 0.137 23.208 ;
     RECT  0.06 23.208 0.137 23.28 ;
     RECT  0.084 23.28 0.137 23.304 ;
     RECT  0.06 23.304 0.137 23.376 ;
     RECT  0.084 23.376 0.137 23.4 ;
     RECT  0.06 23.4 0.137 23.472 ;
     RECT  0.084 23.472 0.137 23.496 ;
     RECT  0.06 23.496 0.137 23.568 ;
     RECT  0.084 23.568 0.137 23.592 ;
     RECT  0.06 23.592 0.137 23.664 ;
     RECT  0.084 23.664 0.137 23.688 ;
     RECT  0.06 23.688 0.137 23.76 ;
     RECT  0.084 23.76 0.137 23.784 ;
     RECT  0.06 23.784 0.137 23.856 ;
     RECT  0.084 23.856 0.137 23.88 ;
     RECT  0.06 23.88 0.137 23.952 ;
     RECT  0.084 23.952 0.137 23.976 ;
     RECT  0.06 23.976 0.137 24.048 ;
     RECT  0.084 24.048 0.137 24.072 ;
     RECT  0.06 24.072 0.137 24.144 ;
     RECT  0.084 24.144 0.137 24.168 ;
     RECT  0.06 24.168 0.137 24.24 ;
     RECT  0.084 24.24 0.137 24.264 ;
     RECT  0.06 24.264 0.137 24.336 ;
     RECT  0.084 24.336 0.137 24.36 ;
     RECT  0.06 24.36 0.137 24.432 ;
     RECT  0.084 24.432 0.137 24.456 ;
     RECT  0.06 24.456 0.137 24.528 ;
     RECT  0.084 24.528 0.137 24.552 ;
     RECT  0.06 24.552 0.137 24.624 ;
     RECT  0.084 24.624 0.137 24.648 ;
     RECT  0.06 24.648 0.137 24.72 ;
     RECT  0.084 24.72 0.137 24.744 ;
     RECT  0.06 24.744 0.137 24.816 ;
     RECT  0.084 24.816 0.137 24.84 ;
     RECT  0.06 24.84 0.137 24.912 ;
     RECT  0.084 24.912 0.137 24.936 ;
     RECT  0.06 24.936 0.137 25.008 ;
     RECT  0.084 25.008 0.137 25.032 ;
     RECT  0.06 25.032 0.137 25.104 ;
     RECT  0.084 25.104 0.137 25.128 ;
     RECT  0.06 25.128 0.137 25.2 ;
     RECT  0.084 25.2 0.137 25.224 ;
     RECT  0.06 25.224 0.137 25.296 ;
     RECT  0.084 25.296 0.137 25.32 ;
     RECT  0.06 25.32 0.137 25.392 ;
     RECT  0.084 25.392 0.137 25.416 ;
     RECT  0.06 25.416 0.137 25.488 ;
     RECT  0.084 25.488 0.137 25.512 ;
     RECT  0.137 22.56 1.141 25.512 ;
     RECT  0.084 9.456 2.293 9.48 ;
     RECT  0.06 9.48 2.293 9.552 ;
     RECT  0.084 9.552 2.293 9.576 ;
     RECT  0.06 9.576 2.293 9.648 ;
     RECT  0.084 9.648 2.293 9.672 ;
     RECT  0.06 9.672 2.293 9.744 ;
     RECT  0.084 9.744 2.293 9.768 ;
     RECT  0.06 9.768 2.293 9.84 ;
     RECT  0.084 9.84 2.293 9.864 ;
     RECT  0.06 9.864 2.293 9.936 ;
     RECT  0.084 9.936 2.293 9.96 ;
     RECT  0.06 9.96 2.293 10.032 ;
     RECT  0.084 10.032 2.293 10.056 ;
     RECT  0.06 10.056 2.293 10.128 ;
     RECT  0.084 10.128 2.293 10.152 ;
     RECT  0.06 10.152 2.293 10.224 ;
     RECT  0.084 10.224 2.293 10.248 ;
     RECT  0.06 10.248 2.293 10.32 ;
     RECT  0.084 10.32 2.293 10.344 ;
     RECT  0.06 10.344 2.293 10.416 ;
     RECT  0.084 10.416 2.293 10.44 ;
     RECT  0.06 10.44 2.293 10.512 ;
     RECT  0.084 10.512 2.293 10.536 ;
     RECT  0.06 10.536 2.293 10.608 ;
     RECT  0.084 10.608 2.293 10.632 ;
     RECT  0.06 10.632 2.293 10.704 ;
     RECT  0.084 10.704 2.293 10.728 ;
     RECT  0.06 10.728 2.293 10.8 ;
     RECT  0.084 10.8 2.293 10.824 ;
     RECT  0.06 10.824 2.293 10.896 ;
     RECT  0.084 10.896 2.293 10.92 ;
     RECT  0.06 10.92 2.293 10.992 ;
     RECT  0.084 10.992 2.293 11.016 ;
     RECT  0.06 11.016 2.293 11.088 ;
     RECT  0.084 11.088 2.293 11.112 ;
     RECT  0.06 11.112 2.293 11.184 ;
     RECT  0.084 11.184 2.293 11.208 ;
     RECT  0.06 11.208 2.293 11.28 ;
     RECT  0.084 11.28 2.293 11.304 ;
     RECT  0.06 11.304 2.293 11.376 ;
     RECT  0.084 11.376 2.293 11.4 ;
     RECT  0.06 11.4 2.293 11.472 ;
     RECT  0.084 11.472 2.293 11.496 ;
     RECT  0.06 11.496 2.293 11.568 ;
     RECT  0.084 11.568 2.293 11.592 ;
     RECT  0.06 11.592 2.293 11.664 ;
     RECT  0.084 11.664 2.293 11.688 ;
     RECT  0.06 11.688 2.293 11.76 ;
     RECT  0.084 11.76 2.293 11.784 ;
     RECT  0.06 11.784 2.293 11.856 ;
     RECT  0.084 11.856 2.293 11.88 ;
     RECT  0.06 11.88 2.293 11.952 ;
     RECT  0.084 11.952 2.293 11.976 ;
     RECT  0.06 11.976 2.293 12.048 ;
     RECT  0.084 12.048 2.293 12.072 ;
     RECT  0.06 12.072 2.293 12.144 ;
     RECT  0.084 12.144 2.293 12.168 ;
     RECT  0.06 12.168 2.293 12.24 ;
     RECT  0.084 12.24 2.293 12.264 ;
     RECT  0.06 12.264 2.293 12.336 ;
     RECT  0.084 12.336 2.293 12.36 ;
     RECT  0.06 12.36 2.293 12.432 ;
     RECT  0.084 12.432 2.293 12.456 ;
     RECT  0.084 3.312 2.408 3.336 ;
     RECT  0.06 3.336 2.408 3.408 ;
     RECT  0.084 3.408 2.408 3.432 ;
     RECT  0.06 3.432 2.408 3.504 ;
     RECT  0.084 3.504 2.408 3.528 ;
     RECT  0.06 3.528 2.408 3.6 ;
     RECT  0.084 3.6 2.408 3.624 ;
     RECT  0.06 3.624 2.408 3.696 ;
     RECT  0.084 3.696 2.408 3.72 ;
     RECT  0.06 3.72 2.408 3.792 ;
     RECT  0.084 3.792 2.408 3.816 ;
     RECT  0.06 3.816 2.408 3.888 ;
     RECT  0.084 3.888 2.408 3.912 ;
     RECT  0.06 3.912 2.408 3.984 ;
     RECT  0.084 3.984 2.408 4.008 ;
     RECT  0.06 4.008 2.408 4.08 ;
     RECT  0.084 4.08 2.408 4.104 ;
     RECT  0.06 4.104 2.408 4.176 ;
     RECT  0.084 4.176 2.408 4.2 ;
     RECT  0.06 4.2 2.408 4.272 ;
     RECT  0.084 4.272 2.408 4.296 ;
     RECT  0.06 4.296 2.408 4.368 ;
     RECT  0.084 4.368 2.408 4.392 ;
     RECT  0.06 4.392 2.408 4.464 ;
     RECT  0.084 4.464 2.408 4.488 ;
     RECT  0.06 4.488 2.408 4.56 ;
     RECT  0.084 4.56 2.408 4.584 ;
     RECT  0.06 4.584 2.408 4.656 ;
     RECT  0.084 4.656 2.408 4.68 ;
     RECT  0.06 4.68 2.408 4.752 ;
     RECT  0.084 4.752 2.408 4.776 ;
     RECT  0.06 4.776 2.408 4.848 ;
     RECT  0.084 4.848 2.408 4.872 ;
     RECT  0.06 4.872 2.408 4.944 ;
     RECT  0.084 4.944 2.408 4.968 ;
     RECT  0.06 4.968 2.408 5.04 ;
     RECT  0.084 5.04 2.408 5.064 ;
     RECT  0.06 5.064 2.408 5.136 ;
     RECT  0.084 5.136 2.408 5.16 ;
     RECT  0.06 5.16 2.408 5.232 ;
     RECT  0.084 5.232 2.408 5.256 ;
     RECT  0.06 5.256 2.408 5.328 ;
     RECT  0.084 5.328 2.408 5.352 ;
     RECT  0.06 5.352 2.408 5.424 ;
     RECT  0.084 5.424 2.408 5.448 ;
     RECT  0.06 5.448 2.408 5.52 ;
     RECT  0.084 5.52 2.408 5.544 ;
     RECT  0.06 5.544 2.408 5.616 ;
     RECT  0.084 5.616 2.408 5.64 ;
     RECT  0.06 5.64 2.408 5.712 ;
     RECT  0.084 5.712 2.408 5.736 ;
     RECT  0.06 5.736 2.408 5.808 ;
     RECT  0.084 5.808 2.408 5.832 ;
     RECT  0.06 5.832 2.408 5.904 ;
     RECT  0.084 5.904 2.408 5.928 ;
     RECT  0.06 5.928 2.408 6 ;
     RECT  0.084 6 2.408 6.024 ;
     RECT  0.06 6.024 2.408 6.096 ;
     RECT  0.084 6.096 2.408 6.12 ;
     RECT  0.06 6.12 2.408 6.192 ;
     RECT  0.084 6.192 2.408 6.216 ;
     RECT  0.06 6.216 2.408 6.288 ;
     RECT  0.084 6.288 2.408 6.312 ;
     RECT  2.293 9.456 2.408 12.552 ;
     RECT  0.084 15.6 2.408 15.624 ;
     RECT  0.06 15.624 2.408 15.696 ;
     RECT  0.084 15.696 2.408 15.72 ;
     RECT  0.06 15.72 2.408 15.792 ;
     RECT  0.084 15.792 2.408 15.816 ;
     RECT  0.06 15.816 2.408 15.888 ;
     RECT  0.084 15.888 2.408 15.912 ;
     RECT  0.06 15.912 2.408 15.984 ;
     RECT  0.084 15.984 2.408 16.008 ;
     RECT  0.06 16.008 2.408 16.08 ;
     RECT  0.084 16.08 2.408 16.104 ;
     RECT  0.06 16.104 2.408 16.176 ;
     RECT  0.084 16.176 2.408 16.2 ;
     RECT  0.06 16.2 2.408 16.272 ;
     RECT  0.084 16.272 2.408 16.296 ;
     RECT  0.06 16.296 2.408 16.368 ;
     RECT  0.084 16.368 2.408 16.392 ;
     RECT  0.06 16.392 2.408 16.464 ;
     RECT  0.084 16.464 2.408 16.488 ;
     RECT  0.06 16.488 2.408 16.56 ;
     RECT  0.084 16.56 2.408 16.584 ;
     RECT  0.06 16.584 2.408 16.656 ;
     RECT  0.084 16.656 2.408 16.68 ;
     RECT  0.06 16.68 2.408 16.752 ;
     RECT  0.084 16.752 2.408 16.776 ;
     RECT  0.06 16.776 2.408 16.848 ;
     RECT  0.084 16.848 2.408 16.872 ;
     RECT  0.06 16.872 2.408 16.944 ;
     RECT  0.084 16.944 2.408 16.968 ;
     RECT  0.06 16.968 2.408 17.04 ;
     RECT  0.084 17.04 2.408 17.064 ;
     RECT  0.06 17.064 2.408 17.136 ;
     RECT  0.084 17.136 2.408 17.16 ;
     RECT  0.06 17.16 2.408 17.232 ;
     RECT  0.084 17.232 2.408 17.256 ;
     RECT  0.06 17.256 2.408 17.328 ;
     RECT  0.084 17.328 2.408 17.352 ;
     RECT  0.06 17.352 2.408 17.424 ;
     RECT  0.084 17.424 2.408 17.448 ;
     RECT  0.06 17.448 2.408 17.52 ;
     RECT  0.084 17.52 2.408 17.544 ;
     RECT  0.06 17.544 2.408 17.616 ;
     RECT  0.084 17.616 2.408 17.64 ;
     RECT  0.06 17.64 2.408 17.712 ;
     RECT  0.084 17.712 2.408 17.736 ;
     RECT  0.06 17.736 2.408 17.808 ;
     RECT  0.084 17.808 2.408 17.832 ;
     RECT  0.06 17.832 2.408 17.904 ;
     RECT  0.084 17.904 2.408 17.928 ;
     RECT  0.06 17.928 2.408 18 ;
     RECT  0.084 18 2.408 18.024 ;
     RECT  0.06 18.024 2.408 18.096 ;
     RECT  0.084 18.096 2.408 18.12 ;
     RECT  0.06 18.12 2.408 18.192 ;
     RECT  0.084 18.192 2.408 18.216 ;
     RECT  0.06 18.216 2.408 18.288 ;
     RECT  0.084 18.288 2.408 18.312 ;
     RECT  0.06 18.312 2.408 18.384 ;
     RECT  0.084 18.384 2.408 18.408 ;
     RECT  0.06 18.408 2.408 18.48 ;
     RECT  0.084 18.48 2.408 18.504 ;
     RECT  0.06 18.504 2.408 18.576 ;
     RECT  0.084 18.576 2.408 18.6 ;
     RECT  0.06 18.6 2.408 18.672 ;
     RECT  0.084 18.672 2.408 18.696 ;
     RECT  0.06 18.696 2.408 18.768 ;
     RECT  0.084 18.768 2.408 18.792 ;
     RECT  0.06 18.792 2.408 18.864 ;
     RECT  0.084 18.864 2.408 18.888 ;
     RECT  0.06 18.888 2.408 18.96 ;
     RECT  0.084 18.96 2.408 18.984 ;
     RECT  0.06 18.984 2.408 19.056 ;
     RECT  0.084 19.056 2.408 19.08 ;
     RECT  0.06 19.08 2.408 19.152 ;
     RECT  0.084 19.152 2.408 19.176 ;
     RECT  0.06 19.176 2.408 19.248 ;
     RECT  0.084 19.248 2.408 19.272 ;
     RECT  0.06 19.272 2.408 19.344 ;
     RECT  0.084 19.344 2.408 19.368 ;
     RECT  1.141 22.512 2.408 25.512 ;
     RECT  2.408 2.148 2.512 30.252 ;
     RECT  2.512 2.418 2.704 29.982 ;
     RECT  2.704 27.168 3.443 28.152 ;
     RECT  2.704 2.784 3.587 6.12 ;
     RECT  3.587 3.312 3.697 6.12 ;
     RECT  2.704 15.792 3.845 19.416 ;
     RECT  2.704 21.12 4.057 21.144 ;
     RECT  2.704 22.512 4.057 25.8 ;
     RECT  2.704 7.968 4.201 7.992 ;
     RECT  2.704 9.6 4.201 12.504 ;
     RECT  2.704 29.184 4.309 29.208 ;
     RECT  4.201 7.968 4.453 12.504 ;
     RECT  4.057 21.12 4.489 25.8 ;
     RECT  4.129 14.64 4.525 14.664 ;
     RECT  3.845 15.792 4.525 19.368 ;
     RECT  3.697 3.312 4.559 6.312 ;
     RECT  4.453 7.392 4.559 12.504 ;
     RECT  4.489 20.976 4.669 25.8 ;
     RECT  4.525 14.64 4.837 19.368 ;
     RECT  4.669 20.592 4.837 25.8 ;
     RECT  4.559 3.312 4.993 12.504 ;
     RECT  4.993 3.024 5.029 12.504 ;
     RECT  4.921 13.632 5.029 13.656 ;
     RECT  5.029 3.024 5.108 13.656 ;
     RECT  4.837 14.64 5.108 25.8 ;
     RECT  3.443 27.168 5.108 27.72 ;
     RECT  4.309 28.8 5.108 29.208 ;
     RECT  5.108 2.148 5.212 30.252 ;
     RECT  5.212 2.418 5.404 29.982 ;
     RECT  5.404 28.8 5.537 28.824 ;
     RECT  5.404 8.448 5.681 27.624 ;
     RECT  5.681 19.68 5.717 27.624 ;
     RECT  5.681 8.448 5.861 18.504 ;
     RECT  5.404 2.832 6.131 7.416 ;
     RECT  6.131 2.832 6.293 6.888 ;
     RECT  6.293 2.832 6.685 6.84 ;
     RECT  5.717 19.68 6.757 24.552 ;
     RECT  5.717 25.536 6.757 27.624 ;
     RECT  5.861 8.448 6.901 18.024 ;
     RECT  6.901 8.448 6.973 18.696 ;
     RECT  6.757 19.68 6.973 27.624 ;
     RECT  6.973 8.448 7.405 27.624 ;
     RECT  7.405 8.448 7.441 27.912 ;
     RECT  7.441 8.448 7.513 28.632 ;
     RECT  6.685 2.304 7.808 6.84 ;
     RECT  7.513 7.92 7.808 28.632 ;
     RECT  7.808 2.148 7.912 30.252 ;
     RECT  7.912 2.304 8.104 29.982 ;
     RECT  8.104 2.304 8.243 24.072 ;
     RECT  8.243 8.448 8.483 24.072 ;
     RECT  8.483 8.448 8.669 23.4 ;
     RECT  8.243 2.304 8.705 7.416 ;
     RECT  8.104 25.056 8.849 29.016 ;
     RECT  8.669 8.448 9.241 13.416 ;
     RECT  8.705 2.304 9.245 6.84 ;
     RECT  8.849 25.056 9.461 28.728 ;
     RECT  8.669 14.448 9.565 23.4 ;
     RECT  9.565 14.448 9.673 23.544 ;
     RECT  9.245 2.544 9.997 6.84 ;
     RECT  9.241 8.16 9.997 13.416 ;
     RECT  9.673 14.448 10.213 23.688 ;
     RECT  10.213 14.448 10.357 23.88 ;
     RECT  9.997 2.544 10.508 13.416 ;
     RECT  10.357 14.448 10.508 23.928 ;
     RECT  9.461 25.248 10.508 28.728 ;
     RECT  10.508 2.148 10.612 30.252 ;
     RECT  10.612 2.418 10.804 29.982 ;
     RECT  10.804 9.264 11.549 28.824 ;
     RECT  10.804 2.496 11.801 7.896 ;
     RECT  11.801 2.784 11.843 7.896 ;
     RECT  11.549 9.264 11.981 19.944 ;
     RECT  11.843 2.784 12.053 7.368 ;
     RECT  11.549 20.928 12.179 28.824 ;
     RECT  12.179 21.648 12.197 28.824 ;
     RECT  11.981 9.6 12.913 19.944 ;
     RECT  12.053 4.512 13.093 7.368 ;
     RECT  12.197 21.696 13.165 28.824 ;
     RECT  12.053 2.784 13.208 3.384 ;
     RECT  13.093 4.512 13.208 8.184 ;
     RECT  12.913 9.6 13.208 20.088 ;
     RECT  13.165 21.696 13.208 29.784 ;
     RECT  13.208 2.148 13.312 30.252 ;
     RECT  13.312 2.304 13.504 29.982 ;
     RECT  13.504 21.696 14.069 28.728 ;
     RECT  13.504 2.304 14.321 7.368 ;
     RECT  14.069 25.536 14.429 28.728 ;
     RECT  13.504 9.6 14.465 20.088 ;
     RECT  14.069 21.696 14.465 23.688 ;
     RECT  13.504 8.448 14.581 8.568 ;
     RECT  14.465 9.6 14.581 19.944 ;
     RECT  14.321 2.784 14.629 7.368 ;
     RECT  14.581 8.448 14.629 19.944 ;
     RECT  14.629 2.784 14.675 19.944 ;
     RECT  14.675 9.12 14.689 19.944 ;
     RECT  14.465 21.696 14.713 23.64 ;
     RECT  14.713 21.312 14.933 23.64 ;
     RECT  14.933 21.552 15.445 23.64 ;
     RECT  14.429 25.536 15.541 28.536 ;
     RECT  13.504 29.76 15.541 29.784 ;
     RECT  14.689 9.552 15.721 19.944 ;
     RECT  15.445 21.552 15.781 24.072 ;
     RECT  15.541 25.536 15.781 29.784 ;
     RECT  14.675 2.784 15.908 7.992 ;
     RECT  15.721 9.12 15.908 19.944 ;
     RECT  15.781 21.552 15.908 29.784 ;
     RECT  15.908 2.148 16.012 30.252 ;
     RECT  16.012 2.256 16.204 29.982 ;
     RECT  16.204 25.536 16.589 28.968 ;
     RECT  16.204 21.072 16.805 23.832 ;
     RECT  16.204 2.256 16.913 7.176 ;
     RECT  16.204 9.216 17.489 19.944 ;
     RECT  16.204 8.16 17.629 8.184 ;
     RECT  16.805 21.696 17.629 23.832 ;
     RECT  16.913 2.352 17.881 7.176 ;
     RECT  17.629 8.16 17.881 8.472 ;
     RECT  16.589 26.4 17.953 28.968 ;
     RECT  17.953 26.4 18.061 29.352 ;
     RECT  17.629 21.696 18.229 24.648 ;
     RECT  17.489 9.6 18.241 19.944 ;
     RECT  18.229 21.408 18.241 24.648 ;
     RECT  17.881 2.352 18.608 8.472 ;
     RECT  18.241 9.6 18.608 24.648 ;
     RECT  18.061 26.352 18.608 29.352 ;
     RECT  18.608 2.148 18.712 30.252 ;
     RECT  18.712 2.418 18.904 29.982 ;
     RECT  18.904 26.304 18.965 29.304 ;
     RECT  18.904 2.544 19.073 25.08 ;
     RECT  18.965 26.304 19.145 28.536 ;
     RECT  19.073 2.544 19.181 7.416 ;
     RECT  19.073 8.448 19.283 25.08 ;
     RECT  19.181 2.832 19.685 7.416 ;
     RECT  19.685 2.832 19.715 5.352 ;
     RECT  19.957 29.664 20.045 29.688 ;
     RECT  19.283 8.832 20.149 25.08 ;
     RECT  19.145 26.304 20.149 28.488 ;
     RECT  19.715 2.832 20.153 5.304 ;
     RECT  20.149 8.832 20.437 28.488 ;
     RECT  19.685 6.336 20.588 7.416 ;
     RECT  20.437 8.496 20.588 28.488 ;
     RECT  20.153 2.832 21.149 3.96 ;
     RECT  21.149 2.784 21.157 3.96 ;
     RECT  20.153 4.992 21.157 5.304 ;
     RECT  21.157 2.784 21.265 5.304 ;
     RECT  20.588 6.336 21.265 28.488 ;
     RECT  21.265 2.784 21.308 28.488 ;
     RECT  21.308 2.148 21.412 30.252 ;
     RECT  21.412 2.418 21.604 29.982 ;
     RECT  21.604 2.832 21.773 29.784 ;
     RECT  21.773 25.632 21.989 29.784 ;
     RECT  21.989 26.112 22.421 29.784 ;
     RECT  21.773 2.832 22.597 12.072 ;
     RECT  22.597 2.784 22.849 12.072 ;
     RECT  21.773 13.296 22.849 24.504 ;
     RECT  22.849 2.784 22.957 24.936 ;
     RECT  22.421 26.112 23.033 29.592 ;
     RECT  22.957 2.784 24.008 25.032 ;
     RECT  23.033 26.112 24.008 29.016 ;
     RECT  24.008 2.148 24.112 30.252 ;
     RECT  24.112 2.256 24.304 29.982 ;
     RECT  24.304 21.168 24.445 28.536 ;
     RECT  24.304 2.256 24.473 19.896 ;
     RECT  24.473 2.256 24.833 7.176 ;
     RECT  24.304 29.76 25.165 29.784 ;
     RECT  24.445 21.168 25.589 28.488 ;
     RECT  25.589 25.008 25.625 28.488 ;
     RECT  24.473 8.16 25.837 19.896 ;
     RECT  25.589 21.168 25.837 23.592 ;
     RECT  24.833 2.832 25.981 7.176 ;
     RECT  25.837 8.16 25.981 23.592 ;
     RECT  16.357 32.256 26.561 32.28 ;
     RECT  25.981 2.832 26.581 23.592 ;
     RECT  25.625 25.488 26.581 28.488 ;
     RECT  26.581 25.488 26.665 28.728 ;
     RECT  26.581 2.832 26.708 23.928 ;
     RECT  26.665 25.488 26.708 29.64 ;
     RECT  26.708 2.148 26.812 30.252 ;
     RECT  26.812 2.418 27.004 29.982 ;
     RECT  27.004 13.104 27.605 19.896 ;
     RECT  27.004 20.88 27.821 29.64 ;
     RECT  27.004 3.12 27.997 11.784 ;
     RECT  27.821 25.44 28.001 28.536 ;
     RECT  27.821 29.616 28.001 29.64 ;
     RECT  27.821 20.88 28.253 24.216 ;
     RECT  28.001 25.488 28.253 28.536 ;
     RECT  28.253 25.536 28.361 28.344 ;
     RECT  27.605 13.344 28.969 19.896 ;
     RECT  28.253 20.88 28.969 23.928 ;
     RECT  27.997 3.12 29.113 12.36 ;
     RECT  28.969 13.344 29.113 23.928 ;
     RECT  29.113 3.12 29.408 23.928 ;
     RECT  28.361 26.208 29.408 28.344 ;
     RECT  29.408 2.148 29.512 30.252 ;
     RECT  29.512 2.418 29.704 29.982 ;
     RECT  29.704 21.504 29.837 22.584 ;
     RECT  29.704 3.552 30.269 20.424 ;
     RECT  29.704 23.568 30.805 28.2 ;
     RECT  30.805 23.568 30.845 28.392 ;
     RECT  29.837 21.648 30.877 22.584 ;
     RECT  30.845 23.568 30.877 23.736 ;
     RECT  30.877 21.648 30.881 23.736 ;
     RECT  30.845 24.864 30.953 28.392 ;
     RECT  30.953 24.864 31.133 27.72 ;
     RECT  30.269 10.128 31.813 20.424 ;
     RECT  31.813 9.888 31.993 20.424 ;
     RECT  30.881 21.744 32.029 23.736 ;
     RECT  30.269 3.552 32.108 8.76 ;
     RECT  31.993 9.792 32.108 20.424 ;
     RECT  32.029 21.744 32.108 24.504 ;
     RECT  31.133 25.536 32.108 27.72 ;
     RECT  32.108 2.148 32.212 30.252 ;
     RECT  32.212 2.418 32.404 29.982 ;
     RECT  32.404 8.736 33.005 25.08 ;
     RECT  33.005 21.744 33.113 25.08 ;
     RECT  33.113 21.744 33.373 23.976 ;
     RECT  33.005 8.736 34.369 20.424 ;
     RECT  33.373 21.744 34.621 23.112 ;
     RECT  34.369 8.496 34.652 20.424 ;
     RECT  34.621 21.408 34.652 23.112 ;
     RECT  32.404 3.888 34.808 3.96 ;
     RECT  32.404 5.52 34.808 5.544 ;
     RECT  32.404 7.152 34.808 7.368 ;
     RECT  34.652 8.496 34.808 23.112 ;
     RECT  33.113 25.056 34.808 25.08 ;
     RECT  32.404 26.256 34.808 27.624 ;
     RECT  34.808 2.148 34.912 30.252 ;
     RECT  34.912 2.418 35.104 29.982 ;
     RECT  35.104 13.248 35.315 23.4 ;
     RECT  35.315 13.248 35.356 22.824 ;
     RECT  35.104 24.48 35.885 25.08 ;
     RECT  35.104 7.152 35.921 11.688 ;
     RECT  35.921 7.152 36.389 11.352 ;
     RECT  35.356 13.248 36.745 22.584 ;
     RECT  36.389 10.944 37.045 11.352 ;
     RECT  36.745 12.72 37.045 22.584 ;
     RECT  37.045 10.944 37.213 22.584 ;
     RECT  35.104 3.888 37.508 3.96 ;
     RECT  35.104 5.52 37.508 5.544 ;
     RECT  36.389 7.152 37.508 9.912 ;
     RECT  37.213 10.944 37.508 23.304 ;
     RECT  35.885 24.48 37.508 24.504 ;
     RECT  35.104 26.256 37.508 27.624 ;
     RECT  37.508 2.148 37.612 30.252 ;
     RECT  37.612 2.418 37.804 29.982 ;
     RECT  37.804 10.944 37.937 12.264 ;
     RECT  37.804 19.872 37.973 20.328 ;
     RECT  37.804 13.296 38.045 18.264 ;
     RECT  37.804 21.696 38.153 23.304 ;
     RECT  38.045 13.296 38.369 17.976 ;
     RECT  38.369 13.296 38.441 16.92 ;
     RECT  37.937 12.048 38.837 12.264 ;
     RECT  38.441 13.296 38.981 15.576 ;
     RECT  38.981 13.296 39.157 15.288 ;
     RECT  37.804 7.152 39.913 9.576 ;
     RECT  39.157 12.864 40.165 15.288 ;
     RECT  37.804 3.888 40.208 3.96 ;
     RECT  37.804 5.52 40.208 5.544 ;
     RECT  39.913 6.864 40.208 9.576 ;
     RECT  37.937 10.944 40.208 11.016 ;
     RECT  40.165 12.864 40.208 15.528 ;
     RECT  38.441 16.656 40.208 16.92 ;
     RECT  38.369 17.952 40.208 17.976 ;
     RECT  37.973 19.872 40.208 19.896 ;
     RECT  38.153 21.696 40.208 22.584 ;
     RECT  37.804 26.256 40.208 27.624 ;
     RECT  40.208 2.148 40.312 30.252 ;
     RECT  40.312 2.418 40.504 29.982 ;
     RECT  40.504 26.256 41.533 27.624 ;
     RECT  40.504 6.864 41.569 9.672 ;
     RECT  41.533 26.16 41.569 27.816 ;
     RECT  41.569 26.064 41.605 28.488 ;
     RECT  40.504 19.872 42.145 20.136 ;
     RECT  40.504 21.264 42.145 22.584 ;
     RECT  42.145 19.872 42.325 22.584 ;
     RECT  42.325 19.872 42.361 22.824 ;
     RECT  40.504 3.888 42.977 3.96 ;
     RECT  42.361 19.872 42.977 22.92 ;
     RECT  40.504 5.52 43.085 5.544 ;
     RECT  40.504 13.008 43.116 13.032 ;
     RECT  40.504 13.032 43.121 13.104 ;
     RECT  40.504 13.104 43.116 13.128 ;
     RECT  40.504 13.128 43.121 13.2 ;
     RECT  40.504 13.2 43.116 13.224 ;
     RECT  40.504 13.224 43.121 13.296 ;
     RECT  40.504 13.296 43.116 13.32 ;
     RECT  40.504 13.32 43.121 13.392 ;
     RECT  40.504 13.392 43.116 13.416 ;
     RECT  40.504 13.416 43.121 13.488 ;
     RECT  40.504 13.488 43.116 13.512 ;
     RECT  40.504 13.512 43.121 13.584 ;
     RECT  40.504 13.584 43.116 13.608 ;
     RECT  40.504 13.608 43.121 13.68 ;
     RECT  40.504 13.68 43.116 13.704 ;
     RECT  40.504 13.704 43.121 13.776 ;
     RECT  40.504 13.776 43.116 13.8 ;
     RECT  40.504 13.8 43.121 13.872 ;
     RECT  40.504 13.872 43.116 13.896 ;
     RECT  40.504 13.896 43.121 13.968 ;
     RECT  40.504 13.968 43.116 13.992 ;
     RECT  40.504 13.992 43.121 14.064 ;
     RECT  40.504 14.064 43.116 14.088 ;
     RECT  40.504 14.088 43.121 14.16 ;
     RECT  40.504 14.16 43.116 14.184 ;
     RECT  40.504 14.184 43.121 14.256 ;
     RECT  40.504 14.256 43.116 14.28 ;
     RECT  40.504 14.28 43.121 14.352 ;
     RECT  40.504 14.352 43.116 14.376 ;
     RECT  40.504 14.376 43.121 14.448 ;
     RECT  40.504 14.448 43.116 14.472 ;
     RECT  40.504 14.472 43.121 14.544 ;
     RECT  40.504 14.544 43.116 14.568 ;
     RECT  40.504 14.568 43.121 14.64 ;
     RECT  40.504 14.64 43.116 14.664 ;
     RECT  40.504 14.664 43.121 14.736 ;
     RECT  40.504 14.736 43.116 14.76 ;
     RECT  40.504 14.76 43.121 14.832 ;
     RECT  40.504 14.832 43.116 14.856 ;
     RECT  40.504 14.856 43.121 14.928 ;
     RECT  40.504 14.928 43.116 14.952 ;
     RECT  40.504 14.952 43.121 15.024 ;
     RECT  40.504 15.024 43.116 15.048 ;
     RECT  40.504 15.048 43.121 15.12 ;
     RECT  40.504 15.12 43.116 15.144 ;
     RECT  40.504 15.144 43.121 15.216 ;
     RECT  40.504 15.216 43.116 15.24 ;
     RECT  40.504 15.24 43.121 15.312 ;
     RECT  40.504 15.312 43.116 15.336 ;
     RECT  40.504 15.336 43.121 15.408 ;
     RECT  40.504 15.408 43.116 15.432 ;
     RECT  40.504 15.432 43.121 15.504 ;
     RECT  40.504 15.504 43.116 15.528 ;
     RECT  40.504 15.528 43.121 15.6 ;
     RECT  40.504 15.6 43.116 15.624 ;
     RECT  40.504 15.624 43.121 15.696 ;
     RECT  40.504 15.696 43.116 15.72 ;
     RECT  40.504 15.72 43.121 15.792 ;
     RECT  40.504 15.792 43.116 15.816 ;
     RECT  40.504 15.816 43.121 15.888 ;
     RECT  40.504 15.888 43.116 15.912 ;
     RECT  40.504 15.912 43.121 15.984 ;
     RECT  40.504 15.984 43.116 16.008 ;
     RECT  40.504 16.008 43.121 16.08 ;
     RECT  40.504 16.08 43.116 16.104 ;
     RECT  40.504 16.104 43.121 16.176 ;
     RECT  40.504 16.176 43.116 16.2 ;
     RECT  40.504 16.2 43.121 16.272 ;
     RECT  40.504 16.272 43.116 16.296 ;
     RECT  40.504 16.296 43.121 16.368 ;
     RECT  40.504 16.368 43.116 16.392 ;
     RECT  40.504 16.392 43.121 16.464 ;
     RECT  40.504 16.464 43.116 16.488 ;
     RECT  40.504 16.488 43.121 16.56 ;
     RECT  40.504 16.56 43.116 16.584 ;
     RECT  40.504 16.584 43.121 16.656 ;
     RECT  40.504 16.656 43.116 16.68 ;
     RECT  40.504 16.68 43.121 16.752 ;
     RECT  40.504 16.752 43.116 16.776 ;
     RECT  40.504 16.776 43.121 16.848 ;
     RECT  40.504 16.848 43.116 16.872 ;
     RECT  40.504 16.872 43.121 16.944 ;
     RECT  40.504 16.944 43.116 16.968 ;
     RECT  40.504 16.968 43.121 17.976 ;
     RECT  42.977 3.888 43.157 3.912 ;
     RECT  43.121 17.952 43.157 17.976 ;
     RECT  41.569 6.864 43.116 6.888 ;
     RECT  41.569 6.888 43.164 6.96 ;
     RECT  41.569 6.96 43.116 6.984 ;
     RECT  41.569 6.984 43.164 7.056 ;
     RECT  41.569 7.056 43.116 7.08 ;
     RECT  41.569 7.08 43.164 7.152 ;
     RECT  41.569 7.152 43.116 7.176 ;
     RECT  41.569 7.176 43.164 7.248 ;
     RECT  41.569 7.248 43.116 7.272 ;
     RECT  41.569 7.272 43.164 7.344 ;
     RECT  41.569 7.344 43.116 7.368 ;
     RECT  41.569 7.368 43.164 7.44 ;
     RECT  41.569 7.44 43.116 7.464 ;
     RECT  41.569 7.464 43.164 7.536 ;
     RECT  41.569 7.536 43.116 7.56 ;
     RECT  41.569 7.56 43.164 7.632 ;
     RECT  41.569 7.632 43.116 7.656 ;
     RECT  41.569 7.656 43.164 7.728 ;
     RECT  41.569 7.728 43.116 7.752 ;
     RECT  41.569 7.752 43.164 7.824 ;
     RECT  41.569 7.824 43.116 7.848 ;
     RECT  41.569 7.848 43.164 7.92 ;
     RECT  41.569 7.92 43.116 7.944 ;
     RECT  41.569 7.944 43.164 8.016 ;
     RECT  41.569 8.016 43.116 8.04 ;
     RECT  41.569 8.04 43.164 8.112 ;
     RECT  41.569 8.112 43.116 8.136 ;
     RECT  41.569 8.136 43.164 8.208 ;
     RECT  41.569 8.208 43.116 8.232 ;
     RECT  41.569 8.232 43.164 8.304 ;
     RECT  41.569 8.304 43.116 8.328 ;
     RECT  41.569 8.328 43.164 8.4 ;
     RECT  41.569 8.4 43.116 8.424 ;
     RECT  41.569 8.424 43.164 8.496 ;
     RECT  41.569 8.496 43.116 8.52 ;
     RECT  41.569 8.52 43.164 8.592 ;
     RECT  41.569 8.592 43.116 8.616 ;
     RECT  41.569 8.616 43.164 8.688 ;
     RECT  41.569 8.688 43.116 8.712 ;
     RECT  41.569 8.712 43.164 8.784 ;
     RECT  41.569 8.784 43.116 8.808 ;
     RECT  41.569 8.808 43.164 8.88 ;
     RECT  41.569 8.88 43.116 8.904 ;
     RECT  41.569 8.904 43.164 8.976 ;
     RECT  41.569 8.976 43.116 9 ;
     RECT  41.569 9 43.164 9.072 ;
     RECT  41.569 9.072 43.116 9.096 ;
     RECT  41.569 9.096 43.164 9.168 ;
     RECT  41.569 9.168 43.116 9.192 ;
     RECT  41.569 9.192 43.164 9.264 ;
     RECT  41.569 9.264 43.116 9.288 ;
     RECT  41.569 9.288 43.164 9.36 ;
     RECT  41.569 9.36 43.116 9.384 ;
     RECT  41.569 9.384 43.164 9.456 ;
     RECT  41.569 9.456 43.116 9.48 ;
     RECT  41.569 9.48 43.164 9.552 ;
     RECT  41.569 9.552 43.116 9.576 ;
     RECT  41.569 9.576 43.164 9.648 ;
     RECT  41.569 9.648 43.116 9.672 ;
     RECT  41.569 9.672 43.164 9.744 ;
     RECT  41.569 9.744 43.116 9.768 ;
     RECT  41.569 9.768 43.164 9.84 ;
     RECT  41.569 9.84 43.116 9.864 ;
     RECT  43.121 13.032 43.164 13.104 ;
     RECT  43.121 13.128 43.164 13.2 ;
     RECT  43.121 13.224 43.164 13.296 ;
     RECT  43.121 13.32 43.164 13.392 ;
     RECT  43.121 13.416 43.164 13.488 ;
     RECT  43.121 13.512 43.164 13.584 ;
     RECT  43.121 13.608 43.164 13.68 ;
     RECT  43.121 13.704 43.164 13.776 ;
     RECT  43.121 13.8 43.164 13.872 ;
     RECT  43.121 13.896 43.164 13.968 ;
     RECT  43.121 13.992 43.164 14.064 ;
     RECT  43.121 14.088 43.164 14.16 ;
     RECT  43.121 14.184 43.164 14.256 ;
     RECT  43.121 14.28 43.164 14.352 ;
     RECT  43.121 14.376 43.164 14.448 ;
     RECT  43.121 14.472 43.164 14.544 ;
     RECT  43.121 14.568 43.164 14.64 ;
     RECT  43.121 14.664 43.164 14.736 ;
     RECT  43.121 14.76 43.164 14.832 ;
     RECT  43.121 14.856 43.164 14.928 ;
     RECT  43.121 14.952 43.164 15.024 ;
     RECT  43.121 15.048 43.164 15.12 ;
     RECT  43.121 15.144 43.164 15.216 ;
     RECT  43.121 15.24 43.164 15.312 ;
     RECT  43.121 15.336 43.164 15.408 ;
     RECT  43.121 15.432 43.164 15.504 ;
     RECT  43.121 15.528 43.164 15.6 ;
     RECT  43.121 15.624 43.164 15.696 ;
     RECT  43.121 15.72 43.164 15.792 ;
     RECT  43.121 15.816 43.164 15.888 ;
     RECT  43.121 15.912 43.164 15.984 ;
     RECT  43.121 16.008 43.164 16.08 ;
     RECT  43.121 16.104 43.164 16.176 ;
     RECT  43.121 16.2 43.164 16.272 ;
     RECT  43.121 16.296 43.164 16.368 ;
     RECT  43.121 16.392 43.164 16.464 ;
     RECT  43.121 16.488 43.164 16.56 ;
     RECT  43.121 16.584 43.164 16.656 ;
     RECT  43.121 16.68 43.164 16.752 ;
     RECT  43.121 16.776 43.164 16.848 ;
     RECT  43.121 16.872 43.164 16.944 ;
     RECT  42.977 19.92 43.116 19.944 ;
     RECT  42.977 19.944 43.164 20.016 ;
     RECT  42.977 20.016 43.116 20.04 ;
     RECT  42.977 20.04 43.164 20.112 ;
     RECT  42.977 20.112 43.116 20.136 ;
     RECT  42.977 20.136 43.164 20.208 ;
     RECT  42.977 20.208 43.116 20.232 ;
     RECT  42.977 20.232 43.164 20.304 ;
     RECT  42.977 20.304 43.116 20.328 ;
     RECT  42.977 20.328 43.164 20.4 ;
     RECT  42.977 20.4 43.116 20.424 ;
     RECT  42.977 20.424 43.164 20.496 ;
     RECT  42.977 20.496 43.116 20.52 ;
     RECT  42.977 20.52 43.164 20.592 ;
     RECT  42.977 20.592 43.116 20.616 ;
     RECT  42.977 20.616 43.164 20.688 ;
     RECT  42.977 20.688 43.116 20.712 ;
     RECT  42.977 20.712 43.164 20.784 ;
     RECT  42.977 20.784 43.116 20.808 ;
     RECT  42.977 20.808 43.164 20.88 ;
     RECT  42.977 20.88 43.116 20.904 ;
     RECT  42.977 20.904 43.164 20.976 ;
     RECT  42.977 20.976 43.116 21 ;
     RECT  42.977 21 43.164 21.072 ;
     RECT  42.977 21.072 43.116 21.096 ;
     RECT  42.977 21.096 43.164 21.168 ;
     RECT  42.977 21.168 43.116 21.192 ;
     RECT  42.977 21.192 43.164 21.264 ;
     RECT  42.977 21.264 43.116 21.288 ;
     RECT  42.977 21.288 43.164 21.36 ;
     RECT  42.977 21.36 43.116 21.384 ;
     RECT  42.977 21.384 43.164 21.456 ;
     RECT  42.977 21.456 43.116 21.48 ;
     RECT  42.977 21.48 43.164 21.552 ;
     RECT  42.977 21.552 43.116 21.576 ;
     RECT  42.977 21.576 43.164 21.648 ;
     RECT  42.977 21.648 43.116 21.672 ;
     RECT  42.977 21.672 43.164 21.744 ;
     RECT  42.977 21.744 43.116 21.768 ;
     RECT  42.977 21.768 43.164 21.84 ;
     RECT  42.977 21.84 43.116 21.864 ;
     RECT  42.977 21.864 43.164 21.936 ;
     RECT  42.977 21.936 43.116 21.96 ;
     RECT  42.977 21.96 43.164 22.032 ;
     RECT  42.977 22.032 43.116 22.056 ;
     RECT  42.977 22.056 43.164 22.128 ;
     RECT  42.977 22.128 43.116 22.152 ;
     RECT  42.977 22.152 43.164 22.224 ;
     RECT  42.977 22.224 43.116 22.248 ;
     RECT  42.977 22.248 43.164 22.32 ;
     RECT  42.977 22.32 43.116 22.344 ;
     RECT  42.977 22.344 43.164 22.416 ;
     RECT  42.977 22.416 43.116 22.44 ;
     RECT  42.977 22.44 43.164 22.512 ;
     RECT  42.977 22.512 43.116 22.536 ;
     RECT  42.977 22.536 43.164 22.608 ;
     RECT  42.977 22.608 43.116 22.632 ;
     RECT  42.977 22.632 43.164 22.704 ;
     RECT  42.977 22.704 43.116 22.728 ;
     RECT  42.977 22.728 43.164 22.8 ;
     RECT  42.977 22.8 43.116 22.824 ;
     RECT  42.977 22.824 43.164 22.896 ;
     RECT  42.977 22.896 43.116 22.92 ;
     RECT  41.605 26.064 43.116 26.088 ;
     RECT  41.605 26.088 43.164 26.16 ;
     RECT  41.605 26.16 43.116 26.184 ;
     RECT  41.605 26.184 43.164 26.256 ;
     RECT  41.605 26.256 43.116 26.28 ;
     RECT  41.605 26.28 43.164 26.352 ;
     RECT  41.605 26.352 43.116 26.376 ;
     RECT  41.605 26.376 43.164 26.448 ;
     RECT  41.605 26.448 43.116 26.472 ;
     RECT  41.605 26.472 43.164 26.544 ;
     RECT  41.605 26.544 43.116 26.568 ;
     RECT  41.605 26.568 43.164 26.64 ;
     RECT  41.605 26.64 43.116 26.664 ;
     RECT  41.605 26.664 43.164 26.736 ;
     RECT  41.605 26.736 43.116 26.76 ;
     RECT  41.605 26.76 43.164 26.832 ;
     RECT  41.605 26.832 43.116 26.856 ;
     RECT  41.605 26.856 43.164 26.928 ;
     RECT  41.605 26.928 43.116 26.952 ;
     RECT  41.605 26.952 43.164 27.024 ;
     RECT  41.605 27.024 43.116 27.048 ;
     RECT  41.605 27.048 43.164 27.12 ;
     RECT  41.605 27.12 43.116 27.144 ;
     RECT  41.605 27.144 43.164 27.216 ;
     RECT  41.605 27.216 43.116 27.24 ;
     RECT  41.605 27.24 43.164 27.312 ;
     RECT  41.605 27.312 43.116 27.336 ;
     RECT  41.605 27.336 43.164 27.408 ;
     RECT  41.605 27.408 43.116 27.432 ;
     RECT  41.605 27.432 43.164 27.504 ;
     RECT  41.605 27.504 43.116 27.528 ;
     RECT  41.605 27.528 43.164 27.6 ;
     RECT  41.605 27.6 43.116 27.624 ;
     RECT  41.605 27.624 43.164 27.696 ;
     RECT  41.605 27.696 43.116 27.72 ;
     RECT  41.605 27.72 43.164 27.792 ;
     RECT  41.605 27.792 43.116 27.816 ;
     RECT  41.605 27.816 43.164 27.888 ;
     RECT  41.605 27.888 43.116 27.912 ;
     RECT  41.605 27.912 43.164 27.984 ;
     RECT  41.605 27.984 43.116 28.008 ;
     RECT  41.605 28.008 43.164 28.08 ;
     RECT  41.605 28.08 43.116 28.104 ;
     RECT  41.605 28.104 43.164 28.176 ;
     RECT  41.605 28.176 43.116 28.2 ;
     RECT  41.605 28.2 43.164 28.272 ;
     RECT  41.605 28.272 43.116 28.296 ;
     RECT  41.605 28.296 43.164 28.368 ;
     RECT  41.605 28.368 43.116 28.392 ;
     RECT  41.605 28.392 43.164 28.464 ;
     RECT  41.605 28.464 43.116 28.488 ;
     RECT  41.605 28.488 43.164 28.56 ;
     RECT  41.605 28.56 43.116 28.584 ;
     RECT  41.605 28.584 43.164 28.656 ;
     RECT  41.605 28.656 43.116 28.68 ;
     RECT  41.605 28.68 43.164 28.752 ;
     RECT  41.605 28.752 43.116 28.776 ;
     RECT  41.605 28.776 43.164 28.848 ;
     RECT  41.605 28.848 43.116 28.872 ;
     RECT  41.605 28.872 43.164 28.944 ;
     RECT  41.605 28.944 43.116 28.968 ;
     RECT  41.605 28.968 43.164 29.04 ;
     RECT  41.605 29.04 43.116 29.064 ;
    LAYER M5 ;
     RECT  2.4 2.137 2.52 2.151 ;
     RECT  5.1 2.137 5.22 2.151 ;
     RECT  7.8 2.137 7.92 2.151 ;
     RECT  10.5 2.137 10.62 2.151 ;
     RECT  13.2 2.137 13.32 2.151 ;
     RECT  15.9 2.137 16.02 2.151 ;
     RECT  18.6 2.137 18.72 2.151 ;
     RECT  21.3 2.137 21.42 2.151 ;
     RECT  24 2.137 24.12 2.151 ;
     RECT  26.7 2.137 26.82 2.151 ;
     RECT  29.4 2.137 29.52 2.151 ;
     RECT  32.1 2.137 32.22 2.151 ;
     RECT  34.8 2.137 34.92 2.151 ;
     RECT  37.5 2.137 37.62 2.151 ;
     RECT  40.2 2.137 40.32 2.151 ;
     RECT  15.9 2.151 16.212 2.245 ;
     RECT  24 2.151 24.312 2.245 ;
     RECT  10.5 2.151 10.812 2.533 ;
     RECT  18.6 2.151 18.912 2.533 ;
     RECT  9.12 2.533 10.812 2.675 ;
     RECT  2.4 2.151 2.712 2.773 ;
     RECT  13.2 2.151 13.512 2.773 ;
     RECT  21.3 2.151 21.612 2.773 ;
     RECT  5.1 2.151 5.412 3.397 ;
     RECT  9.648 2.675 10.812 3.397 ;
     RECT  13.2 2.773 14.28 3.539 ;
     RECT  24 2.245 24.456 3.541 ;
     RECT  24 3.541 25.128 3.683 ;
     RECT  15.9 2.245 16.584 3.829 ;
     RECT  32.1 2.151 32.412 3.829 ;
     RECT  18.48 2.533 18.912 4.211 ;
     RECT  7.8 2.151 8.112 4.213 ;
     RECT  9.648 3.397 11.496 4.259 ;
     RECT  21.168 2.773 21.612 4.259 ;
     RECT  24 3.683 24.456 4.451 ;
     RECT  26.7 2.151 27.012 4.645 ;
     RECT  2.4 2.773 3.576 4.691 ;
     RECT  13.2 3.539 13.512 4.693 ;
     RECT  18.6 4.211 18.912 5.077 ;
     RECT  18.6 5.077 19.704 5.363 ;
     RECT  31.248 3.829 32.412 5.507 ;
     RECT  0.144 5.269 0.168 5.555 ;
     RECT  26.7 4.645 27.144 5.701 ;
     RECT  5.1 3.397 6.312 5.893 ;
     RECT  2.4 4.691 3.432 5.939 ;
     RECT  4.608 5.893 6.312 5.939 ;
     RECT  9.456 5.077 9.48 5.987 ;
     RECT  10.5 4.259 11.496 5.989 ;
     RECT  21.3 4.259 21.612 6.277 ;
     RECT  18.6 5.363 19.416 6.323 ;
     RECT  26.7 5.701 27.672 6.515 ;
     RECT  10.5 5.989 11.976 6.803 ;
     RECT  29.4 2.151 29.712 6.805 ;
     RECT  31.296 5.507 32.412 6.805 ;
     RECT  4.608 5.939 6.12 6.851 ;
     RECT  26.7 6.515 27.144 6.851 ;
     RECT  15.9 3.829 16.824 6.899 ;
     RECT  13.104 4.693 13.512 6.947 ;
     RECT  21.3 6.277 22.104 7.765 ;
     RECT  10.5 6.803 11.832 7.907 ;
     RECT  29.4 6.805 32.412 8.003 ;
     RECT  18.6 6.323 18.912 8.437 ;
     RECT  7.8 4.213 8.232 8.627 ;
     RECT  20.64 7.765 22.104 8.867 ;
     RECT  21.3 8.867 22.104 9.011 ;
     RECT  4.704 6.851 6.12 9.155 ;
     RECT  14.64 7.957 14.664 9.155 ;
     RECT  18.6 8.437 19.272 9.155 ;
     RECT  26.7 6.851 27.012 9.733 ;
     RECT  24 4.451 24.312 10.165 ;
     RECT  26.7 9.733 27.864 10.211 ;
     RECT  14.592 9.349 14.616 10.259 ;
     RECT  5.1 9.155 6.12 10.309 ;
     RECT  4.752 10.309 6.12 10.355 ;
     RECT  18.6 9.155 18.912 10.597 ;
     RECT  29.4 8.003 30.504 10.741 ;
     RECT  24 10.165 24.504 10.933 ;
     RECT  37.5 2.151 37.812 10.981 ;
     RECT  24 10.933 24.6 11.171 ;
     RECT  29.4 10.741 31.128 11.269 ;
     RECT  10.5 7.907 11.688 11.365 ;
     RECT  21.3 9.011 21.612 11.413 ;
     RECT  32.1 8.003 32.412 11.797 ;
     RECT  22.656 10.837 22.68 11.939 ;
     RECT  7.8 8.627 8.112 11.941 ;
     RECT  10.5 11.365 12.168 11.941 ;
     RECT  13.2 6.947 13.512 11.941 ;
     RECT  10.5 11.941 13.512 11.987 ;
     RECT  18.6 10.597 19.368 12.035 ;
     RECT  37.056 10.981 37.812 12.229 ;
     RECT  24 11.171 24.408 12.323 ;
     RECT  28.8 11.269 31.128 12.323 ;
     RECT  32.1 11.797 33.048 12.517 ;
     RECT  7.152 11.941 8.112 12.563 ;
     RECT  28.8 12.323 30.744 12.755 ;
     RECT  37.056 12.229 38.616 12.755 ;
     RECT  9.216 11.557 9.24 12.995 ;
     RECT  21.024 11.413 21.612 13.045 ;
     RECT  26.7 10.211 27.012 13.045 ;
     RECT  10.5 11.987 11.688 13.237 ;
     RECT  13.104 11.987 13.512 13.237 ;
     RECT  10.5 13.237 13.512 13.283 ;
     RECT  28.8 12.755 29.712 13.475 ;
     RECT  22.896 12.757 22.92 13.619 ;
     RECT  4.752 10.355 5.412 13.621 ;
     RECT  7.8 12.563 8.112 13.621 ;
     RECT  37.5 12.755 38.616 13.859 ;
     RECT  18.6 12.035 18.912 14.197 ;
     RECT  34.8 2.151 35.112 14.197 ;
     RECT  34.8 14.197 35.544 14.533 ;
     RECT  30.72 12.755 30.744 14.725 ;
     RECT  10.5 13.283 10.812 14.773 ;
     RECT  12.24 13.283 13.512 14.773 ;
     RECT  30.72 14.725 30.792 14.867 ;
     RECT  4.752 13.621 5.544 14.965 ;
     RECT  17.232 15.013 17.256 15.155 ;
     RECT  15.9 6.899 16.212 15.157 ;
     RECT  7.68 13.621 8.112 15.251 ;
     RECT  26.208 13.045 27.012 15.445 ;
     RECT  26.208 15.445 27.432 15.491 ;
     RECT  10.5 14.773 13.512 15.779 ;
     RECT  20.544 13.045 21.612 15.827 ;
     RECT  32.1 12.517 33.24 16.019 ;
     RECT  4.752 14.965 6.312 16.115 ;
     RECT  18.48 14.197 18.912 16.307 ;
     RECT  7.8 15.251 8.112 16.501 ;
     RECT  4.752 16.115 5.736 16.595 ;
     RECT  22.656 16.069 22.68 16.787 ;
     RECT  26.7 15.491 27.432 16.787 ;
     RECT  40.2 2.151 40.512 16.789 ;
     RECT  24 12.323 24.312 16.885 ;
     RECT  29.4 13.475 29.712 16.885 ;
     RECT  37.5 13.859 37.812 16.885 ;
     RECT  15.9 15.157 16.392 17.077 ;
     RECT  24 16.885 24.888 17.077 ;
     RECT  32.1 16.019 33.096 17.123 ;
     RECT  37.008 16.885 37.812 17.123 ;
     RECT  40.2 16.789 40.92 17.123 ;
     RECT  4.752 16.595 5.544 17.219 ;
     RECT  14.832 16.405 14.856 17.219 ;
     RECT  15.9 17.077 17.064 17.267 ;
     RECT  24 17.077 25.128 17.267 ;
     RECT  28.944 16.885 29.712 17.315 ;
     RECT  1.152 17.365 1.176 17.461 ;
     RECT  0.192 17.461 1.176 17.507 ;
     RECT  32.1 17.123 32.412 17.605 ;
     RECT  0.192 17.507 0.216 17.651 ;
     RECT  4.752 17.219 5.412 17.893 ;
     RECT  4.416 17.893 5.412 18.083 ;
     RECT  12.24 15.779 13.512 18.181 ;
     RECT  21.024 15.827 21.612 18.805 ;
     RECT  12.24 18.181 14.28 18.851 ;
     RECT  25.632 17.845 25.656 18.851 ;
     RECT  34.8 14.533 35.976 19.475 ;
     RECT  12.24 18.851 13.512 19.477 ;
     RECT  30.72 14.867 30.744 19.667 ;
     RECT  21.024 18.805 21.96 19.763 ;
     RECT  34.8 19.475 35.112 19.813 ;
     RECT  12.144 19.477 13.512 19.955 ;
     RECT  10.5 15.779 10.812 19.957 ;
     RECT  21.024 19.763 21.612 20.003 ;
     RECT  36.48 19.813 36.504 20.339 ;
     RECT  26.7 16.787 27.012 20.485 ;
     RECT  29.4 17.315 29.712 20.725 ;
     RECT  18.6 16.307 18.912 20.869 ;
     RECT  15.9 17.267 16.392 21.061 ;
     RECT  37.5 17.123 37.812 21.061 ;
     RECT  25.872 20.485 27.012 21.155 ;
     RECT  10.272 19.957 10.812 21.395 ;
     RECT  18.6 20.869 19.704 21.397 ;
     RECT  29.28 20.725 29.712 21.539 ;
     RECT  36.864 21.061 37.812 21.683 ;
     RECT  7.8 16.501 9.048 21.685 ;
     RECT  7.8 21.685 9.144 22.019 ;
     RECT  22.8 21.877 22.824 22.019 ;
     RECT  15.9 21.061 16.776 22.115 ;
     RECT  7.8 22.019 8.568 22.163 ;
     RECT  15.9 22.115 16.392 22.165 ;
     RECT  18.24 21.397 19.704 22.259 ;
     RECT  34.704 19.813 35.112 22.259 ;
     RECT  18.24 22.259 18.912 22.307 ;
     RECT  13.2 19.955 13.512 22.741 ;
     RECT  31.968 17.605 32.412 22.741 ;
     RECT  34.8 22.259 35.112 22.789 ;
     RECT  6.432 21.829 6.456 22.837 ;
     RECT  7.8 22.163 8.472 22.837 ;
     RECT  10.5 21.395 10.812 22.837 ;
     RECT  4.848 18.083 5.412 22.883 ;
     RECT  26.7 21.155 27.012 23.077 ;
     RECT  9.648 22.837 10.812 23.123 ;
     RECT  6.432 22.837 8.472 23.411 ;
     RECT  34.8 22.789 35.304 23.411 ;
     RECT  15.456 22.165 16.392 23.557 ;
     RECT  24 17.267 24.312 23.701 ;
     RECT  6.864 23.411 8.472 23.843 ;
     RECT  26.592 23.077 27.012 23.845 ;
     RECT  13.2 22.741 13.704 23.891 ;
     RECT  29.4 21.539 29.712 23.893 ;
     RECT  31.968 22.741 33.336 23.987 ;
     RECT  7.248 23.843 8.472 24.083 ;
     RECT  15.456 23.557 17.16 24.083 ;
     RECT  26.592 23.845 27.384 24.563 ;
     RECT  29.4 23.893 29.832 24.611 ;
     RECT  7.248 24.083 8.112 24.659 ;
     RECT  15.792 24.083 17.16 24.659 ;
     RECT  0.144 24.901 0.168 25.091 ;
     RECT  5.1 22.883 5.412 25.093 ;
     RECT  24 23.701 24.408 25.093 ;
     RECT  10.5 23.123 10.812 25.285 ;
     RECT  13.2 23.891 13.512 25.285 ;
     RECT  31.968 23.987 32.412 25.573 ;
     RECT  21.3 20.003 21.612 25.621 ;
     RECT  4.512 25.093 5.412 25.811 ;
     RECT  24 25.093 25.08 25.955 ;
     RECT  12.144 19.955 12.168 26.101 ;
     RECT  13.2 25.285 13.656 26.101 ;
     RECT  26.592 24.563 27.012 26.197 ;
     RECT  31.92 25.573 32.412 26.243 ;
     RECT  12.144 26.101 13.656 26.435 ;
     RECT  14.88 26.245 14.904 26.531 ;
     RECT  13.2 26.435 13.656 26.675 ;
     RECT  7.68 24.659 8.112 26.771 ;
     RECT  21.3 25.621 21.912 26.773 ;
     RECT  21.3 26.773 22.824 26.819 ;
     RECT  26.592 26.197 27.144 26.819 ;
     RECT  22.8 26.819 22.824 26.915 ;
     RECT  2.4 5.939 2.712 27.157 ;
     RECT  12.144 26.435 12.168 27.205 ;
     RECT  19.92 26.485 19.944 27.395 ;
     RECT  12.096 27.205 12.168 27.445 ;
     RECT  13.2 26.675 13.512 27.445 ;
     RECT  10.224 25.285 10.812 27.491 ;
     RECT  12.096 27.445 13.512 27.635 ;
     RECT  15.9 24.659 17.16 27.635 ;
     RECT  7.8 26.771 8.112 27.877 ;
     RECT  2.4 27.157 3.288 28.117 ;
     RECT  21.3 26.819 21.612 28.117 ;
     RECT  24 25.955 24.408 28.261 ;
     RECT  10.5 27.491 10.812 28.453 ;
     RECT  26.592 26.819 27.012 28.453 ;
     RECT  7.68 27.877 8.112 28.643 ;
     RECT  9.648 28.453 10.812 28.739 ;
     RECT  26.592 28.453 27.336 28.739 ;
     RECT  26.7 28.739 27.336 29.123 ;
     RECT  2.4 28.117 3.432 29.219 ;
     RECT  19.968 27.637 19.992 29.699 ;
     RECT  21.3 28.117 22.248 29.795 ;
     RECT  24 28.261 25.128 29.795 ;
     RECT  2.4 29.219 2.712 30.249 ;
     RECT  5.1 25.811 5.412 30.249 ;
     RECT  7.8 28.643 8.112 30.249 ;
     RECT  10.5 28.739 10.812 30.249 ;
     RECT  13.2 27.635 13.512 30.249 ;
     RECT  18.6 22.307 18.912 30.249 ;
     RECT  21.3 29.795 21.612 30.249 ;
     RECT  24 29.795 24.312 30.249 ;
     RECT  26.7 29.123 27.012 30.249 ;
     RECT  29.4 24.611 29.712 30.249 ;
     RECT  32.1 26.243 32.412 30.249 ;
     RECT  34.8 23.411 35.112 30.249 ;
     RECT  37.5 21.683 37.812 30.249 ;
     RECT  40.2 17.123 40.512 30.249 ;
     RECT  2.4 30.249 2.52 30.263 ;
     RECT  5.1 30.249 5.22 30.263 ;
     RECT  7.8 30.249 7.92 30.263 ;
     RECT  10.5 30.249 10.62 30.263 ;
     RECT  13.2 30.249 13.32 30.263 ;
     RECT  15.9 27.635 16.392 30.263 ;
     RECT  18.6 30.249 18.72 30.263 ;
     RECT  21.3 30.249 21.42 30.263 ;
     RECT  24 30.249 24.12 30.263 ;
     RECT  26.7 30.249 26.82 30.263 ;
     RECT  29.4 30.249 29.52 30.263 ;
     RECT  32.1 30.249 32.22 30.263 ;
     RECT  34.8 30.249 34.92 30.263 ;
     RECT  37.5 30.249 37.62 30.263 ;
     RECT  40.2 30.249 40.32 30.263 ;
     RECT  16.368 30.263 16.392 32.291 ;
     RECT  8.112 2.533 9.12 2.675 ;
     RECT  3.576 2.773 5.1 4.691 ;
     RECT  6.312 3.397 7.8 5.939 ;
     RECT  8.232 4.213 9.648 4.259 ;
     RECT  8.232 4.259 10.5 5.077 ;
     RECT  3.432 4.691 5.1 5.893 ;
     RECT  8.232 5.077 9.456 5.987 ;
     RECT  9.48 5.077 10.5 5.987 ;
     RECT  31.248 5.507 31.296 6.805 ;
     RECT  3.432 5.893 4.608 5.939 ;
     RECT  11.976 5.989 13.104 6.803 ;
     RECT  11.832 6.803 13.104 6.947 ;
     RECT  11.832 6.947 13.2 7.907 ;
     RECT  11.688 7.907 13.2 11.365 ;
     RECT  13.512 7.957 14.64 9.155 ;
     RECT  14.664 7.957 15.9 9.155 ;
     RECT  19.272 8.437 20.64 8.867 ;
     RECT  4.752 9.155 5.1 10.309 ;
     RECT  13.512 9.155 15.9 9.349 ;
     RECT  18.912 9.155 19.272 10.597 ;
     RECT  13.512 9.349 14.592 10.259 ;
     RECT  14.616 9.349 15.9 10.259 ;
     RECT  31.128 10.741 32.1 12.323 ;
     RECT  21.612 10.837 22.656 11.939 ;
     RECT  22.68 10.837 24 11.939 ;
     RECT  12.168 11.365 13.2 11.941 ;
     RECT  8.112 11.557 9.216 12.995 ;
     RECT  9.24 11.557 10.5 12.995 ;
     RECT  21.612 11.939 24 12.757 ;
     RECT  11.688 11.987 13.104 13.237 ;
     RECT  30.744 12.323 32.1 14.725 ;
     RECT  7.68 12.563 7.8 13.621 ;
     RECT  29.712 12.755 30.72 19.667 ;
     RECT  21.612 12.757 22.896 13.619 ;
     RECT  22.92 12.757 24 13.619 ;
     RECT  10.812 13.283 12.24 14.773 ;
     RECT  35.976 14.533 37.5 16.885 ;
     RECT  30.792 14.725 32.1 14.867 ;
     RECT  30.744 14.867 32.1 17.605 ;
     RECT  6.312 14.965 7.68 15.251 ;
     RECT  16.212 15.013 17.232 15.155 ;
     RECT  17.256 15.013 18.48 15.155 ;
     RECT  16.212 15.155 16.392 15.157 ;
     RECT  6.312 15.251 7.8 16.115 ;
     RECT  10.812 15.779 12.24 19.477 ;
     RECT  21.612 16.069 22.656 16.787 ;
     RECT  22.68 16.069 24 16.787 ;
     RECT  13.512 16.405 14.832 17.219 ;
     RECT  14.856 16.405 15.9 17.219 ;
     RECT  9.048 16.501 10.5 19.957 ;
     RECT  35.976 16.885 37.008 17.123 ;
     RECT  35.976 17.123 37.5 19.475 ;
     RECT  13.512 17.219 14.28 18.181 ;
     RECT  24.312 17.267 25.128 17.845 ;
     RECT  1.176 17.365 2.4 17.507 ;
     RECT  30.744 17.605 31.968 19.667 ;
     RECT  24.312 17.845 25.632 18.851 ;
     RECT  25.656 17.845 26.7 18.851 ;
     RECT  35.112 19.475 37.5 19.813 ;
     RECT  10.812 19.477 12.144 27.205 ;
     RECT  35.112 19.813 36.48 20.339 ;
     RECT  36.504 19.813 37.5 20.339 ;
     RECT  12.168 19.955 13.2 26.101 ;
     RECT  9.048 19.957 10.272 21.395 ;
     RECT  36.864 20.339 37.5 21.061 ;
     RECT  9.048 21.395 10.5 21.685 ;
     RECT  16.776 21.397 18.24 22.115 ;
     RECT  9.144 21.685 10.5 22.019 ;
     RECT  5.412 21.829 6.432 23.411 ;
     RECT  6.456 21.829 7.8 22.837 ;
     RECT  21.612 21.877 22.8 22.019 ;
     RECT  22.824 21.877 24 22.019 ;
     RECT  8.568 22.019 10.5 22.163 ;
     RECT  16.392 22.115 18.24 22.307 ;
     RECT  8.472 22.163 10.5 22.837 ;
     RECT  34.704 22.259 34.8 22.741 ;
     RECT  16.392 22.307 18.6 23.557 ;
     RECT  33.336 22.741 34.8 23.987 ;
     RECT  8.472 22.837 9.648 23.123 ;
     RECT  5.412 23.411 6.864 23.843 ;
     RECT  17.16 23.557 18.6 27.635 ;
     RECT  13.512 23.891 13.656 25.285 ;
     RECT  25.08 25.093 26.592 25.955 ;
     RECT  13.656 26.245 14.88 26.531 ;
     RECT  14.904 26.245 15.9 26.531 ;
     RECT  12.168 26.435 13.2 27.445 ;
     RECT  18.912 26.485 19.92 27.395 ;
     RECT  19.944 26.485 21.3 27.395 ;
     RECT  7.68 26.771 7.8 27.877 ;
     RECT  22.824 26.773 24 26.915 ;
     RECT  21.612 26.819 22.8 26.915 ;
     RECT  21.612 26.915 22.248 28.117 ;
     RECT  10.812 27.205 12.096 27.635 ;
     RECT  18.912 27.395 21.3 27.637 ;
     RECT  10.224 27.491 10.5 28.453 ;
     RECT  18.912 27.637 19.968 29.699 ;
     RECT  19.992 27.637 21.3 29.699 ;
     RECT  25.128 28.261 26.592 28.739 ;
  END
END hbfd_land_136_EW
END LIBRARY
